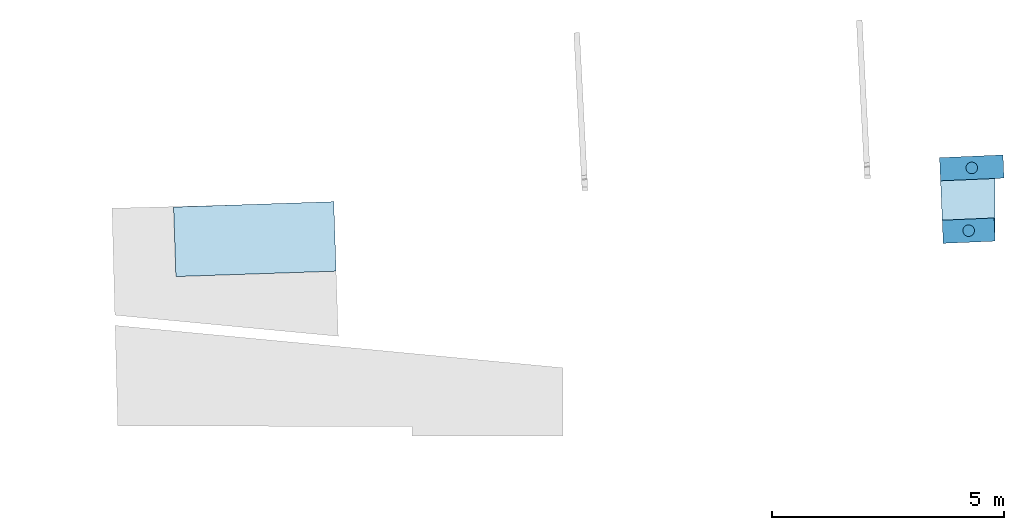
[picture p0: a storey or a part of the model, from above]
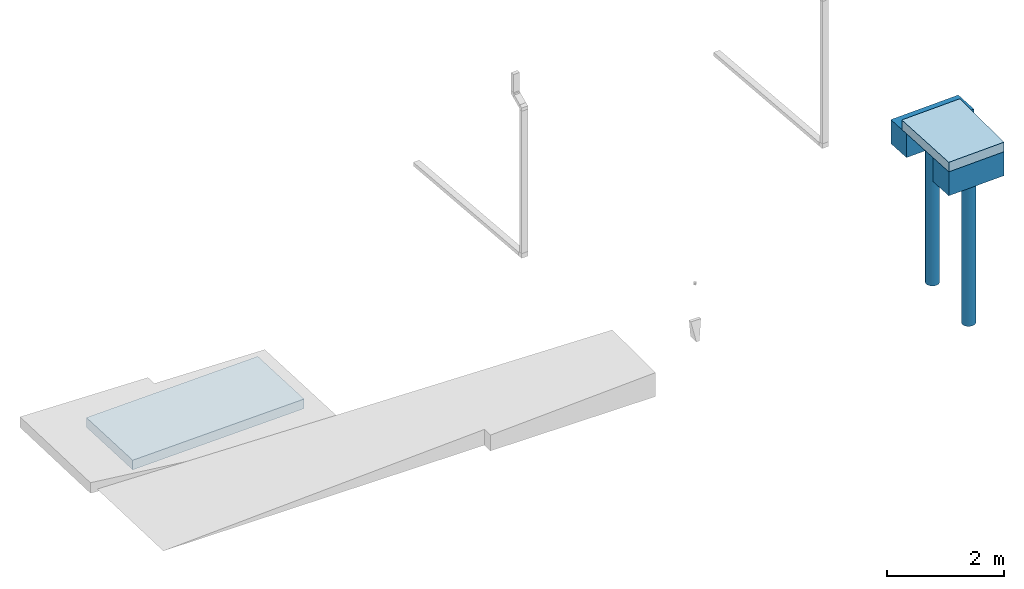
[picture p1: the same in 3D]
Properties of the parts of a building model (IFC2X3), part 1 of 2

# File
Description: ViewDefinition [CoordinationView_V2.0], RevitIdentifiers [ContentGUID: f51560e6-62e8-4d9f-ab56-705ca6fd7212, VersionGUID: 3fd126d5-c997-4c15-8835-0f22745aed74, NumberOfSaves: 71], CoordinateReference [CoordinateBase: Coordonnées partagées actuelles]
File name: 735-CAF31-Ombrière-GO.ifc
Time: 2026-01-16T10:04:22+01:00
Written by: ODA SDAI 24.6
Made in: Autodesk Revit 24.3.10.22 (FRA) - IFC 24.3.20.8

# IfcProject, PRO-DCE
LongName: REAMENAGEMENT DU PARVIS DE LA CAF RUE RIQUET A TOULOUSE; Phase: Etat du projet

# IfcSite, Default
RefLatitude: 48, 51, 57, 604064; RefLongitude: 2, 19, 58, 799800; RefElevation: 0 m

# IfcBuilding
Pset_BuildingCommon - NumberOfStoreys: 3

# IfcBuildingStorey: Niveau:Pointe 8 mm (5)
Name | LongName | Elevation (m)
Fondations | Fondations | -4
00_RDC CAF | 00_RDC CAF | 2.49825e-13
01_N1 CAF | 01_N1 CAF | 4.58
02_N2 CAF | 02_N2 CAF | 7.78
03_N3 CAF | 03_N3 CAF | 10.98

# IfcBeam: Cornière à ailes égales:L150x10 (8)
In: 00_RDC CAF
Type - PredefinedType: BEAM
Type - Pset_BeamCommon - LoadBearing: yes
Material: Acier structurel - S235
Pset_BeamCommon - IsExternal: no; Reference: L150x10
Pset_QuantityTakeOff - Reference: L150x10; sets with these values: 2
Name (Cornière à ailes égales:L150x10:...) | Span (m) | Slope (deg)
832467 | 14.653 | 0.0601116
832659 | 6.1642 | 1.77828
833064 | 3.4381 | 1.77549
833366 | 8.3522 | 0.167103
833582 | 5.8561 | 0
833692 | 1.5976 | 0
834071 | 0.5004 | 0
834376 | 0.5 | 1.7764

# IfcBeam: HE-A:HEA100, HE-A:HEA100:660216
In: 00_RDC CAF
Type - PredefinedType: BEAM
Type - Pset_BeamCommon - LoadBearing: yes
Material: Acier structurel - S235
Pset_BeamCommon - IsExternal: no; Slope: 0 deg; Reference: HEA100; Span: 2.385 m
Pset_QuantityTakeOff - Reference: HEA100; sets with these values: 2

# IfcBeam: IPE:IPE200 (15)
Type - PredefinedType: BEAM
Type - Pset_BeamCommon - LoadBearing: yes
Material: Acier structurel - S235
Pset_BeamCommon - IsExternal: no; Reference: IPE200
Pset_QuantityTakeOff - Reference: IPE200; sets with these values: 2
Name (IPE:IPE200:...) | In | Span (m) | Slope (deg)
616958 | 00_RDC CAF | 4.1239 | 1.77319
624277 | 00_RDC CAF | 0.41 | 1.7764
628714 | 01_N1 CAF | 2.576 | 0.0750055
629145 | 00_RDC CAF | 3.7879 | 1.77825
629344 | 00_RDC CAF | 3.4029 | 1.77558
658623 | 00_RDC CAF | 3.9255 | 1.77629
658634 | 00_RDC CAF | 4.0177 | 1.77553
771490 | 00_RDC CAF | 0.3538 | 1.77537
771715 | 00_RDC CAF | 0.3217 | 1.77558
771726 | 00_RDC CAF | 0.3538 | 1.77825
771738 | 00_RDC CAF | 0.3538 | 1.77871
771752 | 00_RDC CAF | 0.3538 | 1.77552
771776 | 00_RDC CAF | 0.3538 | 1.77317
771792 | 00_RDC CAF | 0.3538 | 1.77828
772215 | 01_N1 CAF | 2.6493 | 0.0729307

# IfcBeam: IPE:IPE240 (5)
In: 00_RDC CAF
Type - PredefinedType: BEAM
Type - Pset_BeamCommon - LoadBearing: yes
Material: Acier structurel - S235
Pset_BeamCommon - IsExternal: no; Reference: IPE240
Pset_QuantityTakeOff - Reference: IPE240; sets with these values: 2
Name (IPE:IPE240:...) | Span (m) | Slope (deg)
613705 | 9.6487 | 0.0765205
615907 | 5.1558 | 0
616066 | 2.1489 | 0.167103
623851 | 4.2305 | 1.77828
625010 | 3.1307 | 1.77549

# IfcBeam: LL-Deux cornières:DCED50x5x10 (6)
In: 00_RDC CAF
Type - PredefinedType: BEAM; Material: Acier structurel - S235
Type - Pset_BeamCommon - LoadBearing: yes
Pset_BeamCommon - IsExternal: no; Reference: DCED50x5x10
Pset_QuantityTakeOff - Reference: DCED50x5x10; sets with these values: 2
Name (LL-Deux cornières:DCED50x5x10:...) | Span (m) | Slope (deg)
689709 | 4.673 | 1.52976
689858 | 4.508 | 1.50344
690037 | 3.53 | 1.21998
690201 | 3.806 | 1.52568
727463 | 4.814 | 1.5502
728095 | 4.763 | 1.48888

# IfcBuildingElementProxy: Eq_Elec_Colonne_Electrique:Eq_Elec_Colonne_Electrique_120x80mm (22)
In: 00_RDC CAF
Type - Material: <Unnamed>
Pset_BuildingElementProxyCommon - Reference: Eq_Elec_Colonne_Electrique_120x80mm; sets with these values: 2
Name (Eq_Elec_Colonne_Electrique:Eq_Elec_Colonne_Electrique_120x80mm:...)
459293
459294
459295
459296
459297
459298
459299
459300
459301
459302
459303
459304
459309
459310
459311
459312
459313
459711
459854
459855
459856
459857

# IfcBuildingElementProxy: Eq_Spe_Plafond_Acoustique_Suspendu:Eq_Spe_Plafond_Acoustique_Suspendu (4)
In: 00_RDC CAF
Type - Material: <Unnamed>
Pset_BuildingElementProxyCommon - Reference: Eq_Spe_Plafond_Acoustique_Suspendu; sets with these values: 2
Name (Eq_Spe_Plafond_Acoustique_Suspendu:Eq_Spe_Plafond_Acoustique_Suspendu:...)
459287
459288
459289
459290

# IfcBuildingElementProxy: Eq_Spe_Plafond_Acoustique_Suspendu:Eq_Spe_Plafond_Acoustique_Suspendu (3)
In: 00_RDC CAF
Type - Material: ARC - Mo - Blanc
Pset_BuildingElementProxyCommon - Reference: Eq_Spe_Plafond_Acoustique_Suspendu; sets with these values: 2
Name (Eq_Spe_Plafond_Acoustique_Suspendu:Eq_Spe_Plafond_Acoustique_Suspendu:...)
459285
459291
459292

# IfcBuildingElementProxy: Profil en relief:M_Profil_Relief_N1 (4)
In: 00_RDC CAF
Material: STR - Beton
Pset_BuildingElementProxyCommon - Reference: M_Profil_Relief_N1; sets with these values: 2
Name (Profil en relief:M_Profil_Relief_N1:...)
459726
459728
459730
459732

# IfcBuildingElementProxy: SENBON Lattice Fence_Reversible Unit_gap 50mm:千本格子リバーシブルユニット 隙間50㎜_H2000 (4)
In: 01_N1 CAF
Type - Material: blackebony
Pset_BuildingElementProxyCommon - Reference: 千本格子リバーシブルユニット 隙間50㎜_H2000; sets with these values: 2
Name (SENBON Lattice Fence_Reversible Unit_gap 50mm:千本格子リバーシブルユニット 隙間50㎜_H2000:...)
690378
729924
730252
730253

# IfcBuildingElementProxy: SENBON Lattice Fence_Reversible Unit_gap 50mm:千本格子リバーシブルユニット 隙間50㎜_H2400, SENBON Lattice Fence_Reversible Unit_gap 50mm:千本格子リバーシブルユニット 隙間50㎜_H2400:726934
In: 01_N1 CAF
Type - Material: blackebony
Pset_BuildingElementProxyCommon - Reference: 千本格子リバーシブルユニット 隙間50㎜_H2400; sets with these values: 2

# IfcColumn: Po_Beton_Rectangulaire:Po_Beton_Rectangulaire_350x400mm, Po_Beton_Rectangulaire:Po_Beton_Rectangulaire_350x400mm:459794
In: 00_RDC CAF
Type - PredefinedType: COLUMN; Material: STR - Beton
Type - Pset_ColumnCommon - LoadBearing: yes
Pset_ColumnCommon - IsExternal: no; Reference: Po_Beton_Rectangulaire_350x400mm
Pset_QuantityTakeOff - Reference: Po_Beton_Rectangulaire_350x400mm; sets with these values: 2

# IfcColumn: Po_Beton_Rectangulaire:Po_Beton_Rectangulaire_400x280mm, Po_Beton_Rectangulaire:Po_Beton_Rectangulaire_400x280mm:459831
In: 00_RDC CAF
Type - PredefinedType: COLUMN; Material: STR - Beton
Type - Pset_ColumnCommon - LoadBearing: yes
Pset_ColumnCommon - IsExternal: no; Reference: Po_Beton_Rectangulaire_400x280mm
Pset_QuantityTakeOff - Reference: Po_Beton_Rectangulaire_400x280mm; sets with these values: 2

# IfcColumn: Po_Beton_Rectangulaire:Po_Beton_Rectangulaire_420x420mm (3)
In: 00_RDC CAF
Type - PredefinedType: COLUMN; Material: STR - Beton
Type - Pset_ColumnCommon - LoadBearing: yes
Pset_ColumnCommon - IsExternal: no; Reference: Po_Beton_Rectangulaire_420x420mm
Pset_QuantityTakeOff - Reference: Po_Beton_Rectangulaire_420x420mm; sets with these values: 2
Name (Po_Beton_Rectangulaire:Po_Beton_Rectangulaire_420x420mm:...)
459618
459792
459793

# IfcColumn: Po_Beton_Rectangulaire:Po_Beton_Rectangulaire_450x300mm (2)
In: 00_RDC CAF
Type - PredefinedType: COLUMN; Material: STR - Beton
Type - Pset_ColumnCommon - LoadBearing: yes
Pset_ColumnCommon - IsExternal: no; Reference: Po_Beton_Rectangulaire_450x300mm
Pset_QuantityTakeOff - Reference: Po_Beton_Rectangulaire_450x300mm; sets with these values: 2
Name (Po_Beton_Rectangulaire:Po_Beton_Rectangulaire_450x300mm:...)
459796
460303

# IfcColumn: Po_Beton_Rectangulaire:Po_Beton_Rectangulaire_450x400mm, Po_Beton_Rectangulaire:Po_Beton_Rectangulaire_450x400mm:459818
In: 00_RDC CAF
Type - PredefinedType: COLUMN; Material: STR - Beton
Type - Pset_ColumnCommon - LoadBearing: yes
Pset_ColumnCommon - IsExternal: no; Reference: Po_Beton_Rectangulaire_450x400mm
Pset_QuantityTakeOff - Reference: Po_Beton_Rectangulaire_450x400mm; sets with these values: 2

# IfcColumn: Po_Beton_Rectangulaire:Po_Beton_Rectangulaire_500x250mm, Po_Beton_Rectangulaire:Po_Beton_Rectangulaire_500x250mm:459820
In: 00_RDC CAF
Type - PredefinedType: COLUMN; Material: STR - Beton
Type - Pset_ColumnCommon - LoadBearing: yes
Pset_ColumnCommon - IsExternal: no; Reference: Po_Beton_Rectangulaire_500x250mm
Pset_QuantityTakeOff - Reference: Po_Beton_Rectangulaire_500x250mm; sets with these values: 2

# IfcColumn: Po_Beton_Rectangulaire:Po_Beton_Rectangulaire_520x420mm, Po_Beton_Rectangulaire:Po_Beton_Rectangulaire_520x420mm:459608
In: 00_RDC CAF
Type - PredefinedType: COLUMN; Material: STR - Beton
Type - Pset_ColumnCommon - LoadBearing: yes
Pset_ColumnCommon - IsExternal: no; Reference: Po_Beton_Rectangulaire_520x420mm
Pset_QuantityTakeOff - Reference: Po_Beton_Rectangulaire_520x420mm; sets with these values: 2

# IfcColumn: Po_Beton_Rectangulaire:Po_Beton_Rectangulaire_530x250mm, Po_Beton_Rectangulaire:Po_Beton_Rectangulaire_530x250mm:460304
In: 00_RDC CAF
Type - PredefinedType: COLUMN; Material: STR - Beton
Type - Pset_ColumnCommon - LoadBearing: yes
Pset_ColumnCommon - IsExternal: no; Reference: Po_Beton_Rectangulaire_530x250mm
Pset_QuantityTakeOff - Reference: Po_Beton_Rectangulaire_530x250mm; sets with these values: 2

# IfcColumn: Po_Beton_Rectangulaire:Po_Beton_Rectangulaire_550x370mm, Po_Beton_Rectangulaire:Po_Beton_Rectangulaire_550x370mm:459795
In: 00_RDC CAF
Type - PredefinedType: COLUMN; Material: STR - Beton
Type - Pset_ColumnCommon - LoadBearing: yes
Pset_ColumnCommon - IsExternal: no; Reference: Po_Beton_Rectangulaire_550x370mm
Pset_QuantityTakeOff - Reference: Po_Beton_Rectangulaire_550x370mm; sets with these values: 2

# IfcColumn: Po_Beton_Rectangulaire:Po_Beton_Rectangulaire_600x300mm (3)
In: 00_RDC CAF
Type - PredefinedType: COLUMN; Material: STR - Beton
Type - Pset_ColumnCommon - LoadBearing: yes
Pset_ColumnCommon - IsExternal: no; Reference: Po_Beton_Rectangulaire_600x300mm
Pset_QuantityTakeOff - Reference: Po_Beton_Rectangulaire_600x300mm; sets with these values: 2
Name (Po_Beton_Rectangulaire:Po_Beton_Rectangulaire_600x300mm:...)
459829
460256
460257

# IfcColumn: Po_Béton_Creusé _Bord:365mm x 385mm (5)
In: 00_RDC CAF
Type - PredefinedType: COLUMN; Material: STR - Beton
Type - Pset_ColumnCommon - LoadBearing: yes
Pset_ColumnCommon - IsExternal: no; Reference: 365mm x 385mm
Pset_QuantityTakeOff - Reference: 365mm x 385mm; sets with these values: 2
Name (Po_Béton_Creusé _Bord:365mm x 385mm:...)
458540
458543
460254
460459
460603

# IfcColumn: Po_Béton_Creusé_Courant:365mm x 385mm (25)
In: 00_RDC CAF
Type - PredefinedType: COLUMN; Material: STR - Beton
Type - Pset_ColumnCommon - LoadBearing: yes
Pset_ColumnCommon - IsExternal: no; Reference: 365mm x 385mm
Pset_QuantityTakeOff - Reference: 365mm x 385mm; sets with these values: 2
Name (Po_Béton_Creusé_Courant:365mm x 385mm:...)
458541
458542
458544
458545
458546
458547
458548
458549
458550
458551
458552
458553
458554
460460
460461
460462
460463
460464
460465
460604
460605
460606
460607
460608
460609

# IfcColumn: Po_Béton_T:365mm x 385mm (26)
In: 00_RDC CAF
Type - PredefinedType: COLUMN; Material: <Unnamed>
Type - Pset_ColumnCommon - LoadBearing: yes
Pset_ColumnCommon - IsExternal: no; Reference: 365mm x 385mm
Pset_QuantityTakeOff - Reference: 365mm x 385mm; sets with these values: 2
Name (Po_Béton_T:365mm x 385mm:...)
458565
458567
458568
458569
458570
458571
458572
458573
458574
458575
458576
458577
459950
459951
460466
460467
460468
460469
460470
460471
460610
460611
460612
460613
460614
460615

# IfcColumn: Poteau HE-A:HEA100 (2)
In: 00_RDC CAF
Type - PredefinedType: COLUMN; Material: Acier structurel - S235
Type - Pset_ColumnCommon - LoadBearing: yes
Pset_ColumnCommon - IsExternal: no; Reference: HEA100
Pset_QuantityTakeOff - Reference: HEA100; sets with these values: 2
Name (Poteau HE-A:HEA100:...)
659574 | Pset_ColumnCommon - Slope: 0 deg
729567

# IfcColumn: Poteau HE-A:HEA120 (5)
In: 00_RDC CAF
Type - PredefinedType: COLUMN; Material: Acier structurel - S235
Type - Pset_ColumnCommon - LoadBearing: yes
Pset_ColumnCommon - IsExternal: no; Slope: 0 deg; Reference: HEA120
Pset_QuantityTakeOff - Reference: HEA120; sets with these values: 2
Name (Poteau HE-A:HEA120:...)
609685
610124
610207
614403
614412

# IfcColumn: Poteau HE-B:HEB100 (5)
In: 00_RDC CAF
Type - PredefinedType: COLUMN; Material: STR - Acier
Type - Pset_ColumnCommon - LoadBearing: yes
Pset_ColumnCommon - IsExternal: no; Reference: HEB100
Pset_QuantityTakeOff - Reference: HEB100; sets with these values: 2
Name (Poteau HE-B:HEB100:...)
459441
459442
459443
459539
459540

# IfcCovering: Faux-Plafond_CAF:Faux-Plafond_CAF, Faux-Plafond_CAF:Faux-Plafond_CAF:458936
In: 00_RDC CAF
Type - PredefinedType: CEILING
Pset_CoveringCommon - Reference: Faux-Plafond_CAF; sets with these values: 2

# IfcCovering: Mur de base:FP_Platre_20mm_Joue_de_plafond (5)
In: 00_RDC CAF
Type - PredefinedType: CEILING; Material: ARC - FP - Blanc 0.02 m
Pset_CoveringCommon - Reference: FP_Platre_20mm_Joue_de_plafond; sets with these values: 2
Name (Mur de base:FP_Platre_20mm_Joue_de_plafond:...)
458953
459178
459197
459819
459888

# IfcCovering: Mur de base:FP_Platre_70mm_Joue_de_plafond (6)
In: 00_RDC CAF
Type - PredefinedType: CEILING; Material: ARC - FP - Blanc 0.07 m
Pset_CoveringCommon - Reference: FP_Platre_70mm_Joue_de_plafond; sets with these values: 2
Name (Mur de base:FP_Platre_70mm_Joue_de_plafond:...)
459209
459690
459691
459692
459693
459826

# IfcCovering: Plafond composé:FP_70mm (2)
In: 00_RDC CAF
Type - PredefinedType: CEILING
Type - Pset_CoveringCommon - TotalThickness: 0.07 m
Material: ARC - FP - Blanc 0.07 m
Pset_CoveringCommon - Reference: FP_70mm; sets with these values: 2
Name (Plafond composé:FP_70mm:...)
458963
459173

# IfcCovering: Plafond composé:FP_Dalle-600X600_70mm (21)
In: 00_RDC CAF
Type - PredefinedType: CEILING
Type - Pset_CoveringCommon - TotalThickness: 0.07 m
Material: ARC - FP - Blanc 0.02 m, ARC - FP - Trame 600 x 600 0.05 m
Pset_CoveringCommon - Reference: FP_Dalle-600X600_70mm; sets with these values: 2
Name (Plafond composé:FP_Dalle-600X600_70mm:...)
458870
458884
458892
458939
458946
458991
459024
459072
459084
459092
459117
459123
459153
459181
459192
459202
459318
459325
459682
460212
460221

# IfcCurtainWall: Mur-rideau:F.Ri._Ext_Vitre_40mm_Montant_100mm (4)
In: 00_RDC CAF
Pset_CurtainWallCommon - IsExternal: yes; Reference: F.Ri._Ext_Vitre_40mm_Montant_100mm
Pset_QuantityTakeOff - Reference: F.Ri._Ext_Vitre_40mm_Montant_100mm
Name (Mur-rideau:F.Ri._Ext_Vitre_40mm_Montant_100mm:...)
459893
459952
709813
709819

# IfcCurtainWall: Mur-rideau:FRi.Ext.30mm Etages (24)
In: 00_RDC CAF
Pset_CurtainWallCommon - IsExternal: yes; Reference: FRi.Ext.30mm Etages
Pset_QuantityTakeOff - Reference: FRi.Ext.30mm Etages
Name (Mur-rideau:FRi.Ext.30mm Etages:...)
460472
460481
460490
460499
460508
460517
460526
460535
460544
460553
460562
460571
460616
460625
460634
460643
460652
460661
460670
460679
460688
460697
460706
460715

# IfcCurtainWall: Mur-rideau:FRi.Ext.30mm RDC (28)
In: 00_RDC CAF
Pset_CurtainWallCommon - IsExternal: yes; Reference: FRi.Ext.30mm RDC
Pset_QuantityTakeOff - Reference: FRi.Ext.30mm RDC
Name (Mur-rideau:FRi.Ext.30mm RDC:...)
458555
458579
458589
458600
458611
458622
458633
458644
458655
458666
458677
458688
458699
458710
458716
458722
458733
458744
458755
458766
458777
458788
458799
458810
459980
459986
459992
459998

# IfcCurtainWall: Mur-rideau:M.Ri._Vitre_40mm_Montant_115mm, Mur-rideau:M.Ri._Vitre_40mm_Montant_115mm:459907
In: 00_RDC CAF
Pset_CurtainWallCommon - IsExternal: no; Reference: M.Ri._Vitre_40mm_Montant_115mm
Pset_QuantityTakeOff - Reference: M.Ri._Vitre_40mm_Montant_115mm

# IfcCurtainWall: Mur-rideau:M.Ri_Ext_Grille_RDC_50mm, Mur-rideau:M.Ri_Ext_Grille_RDC_50mm:460416
In: 00_RDC CAF
Pset_CurtainWallCommon - IsExternal: yes; Reference: M.Ri_Ext_Grille_RDC_50mm
Pset_QuantityTakeOff - Reference: M.Ri_Ext_Grille_RDC_50mm

# IfcCurtainWall: Mur-rideau:M.Ri_Vitre_40mm_Montant_50X50mm_Avec_Décalage (2)
In: 00_RDC CAF
Pset_CurtainWallCommon - IsExternal: no; Reference: M.Ri_Vitre_40mm_Montant_50X50mm_Avec_Décalage
Pset_QuantityTakeOff - Reference: M.Ri_Vitre_40mm_Montant_50X50mm_Avec_Décalage
Name (Mur-rideau:M.Ri_Vitre_40mm_Montant_50X50mm_Avec_Décalage:...)
459713
459750

# IfcCurtainWall: Mur-rideau:M.Ri_Vitre_40mm_Montant_70X90mm (5)
In: 00_RDC CAF
Pset_CurtainWallCommon - IsExternal: no; Reference: M.Ri_Vitre_40mm_Montant_70X90mm
Pset_QuantityTakeOff - Reference: M.Ri_Vitre_40mm_Montant_70X90mm
Name (Mur-rideau:M.Ri_Vitre_40mm_Montant_70X90mm:...)
458839
459337
459362
459387
459412

# IfcCurtainWall: Mur-rideau:M.Ri_Vitré_70mm, Mur-rideau:M.Ri_Vitré_70mm:459870
In: 00_RDC CAF
Pset_CurtainWallCommon - IsExternal: no; Reference: M.Ri_Vitré_70mm
Pset_QuantityTakeOff - Reference: M.Ri_Vitré_70mm

# IfcDistributionPort (57)
Description: Flow; FlowDirection: SOURCEANDSINK
Name | Group
Port_458968_1
Port_458977_1
Port_459947_1
Port_460020_1
Port_460022_1
Port_460023_1
Port_460025_1
Port_460069_1
Port_460070_1
Port_460073_1
Port_460074_1
Port_460076_1
Port_460077_1
Port_460079_1
Port_460080_1
Port_460081_1
Port_460082_1
Port_460083_1
Port_460084_1
Port_460085_1
Port_460086_1
Port_460087_1
Port_460088_1
Port_460089_1
Port_460090_1
Port_460091_1
Port_460092_1
Port_752365_0 | EP GO 2
Port_752365_1 | EP GO 2
Port_819100_0 | SF 2
Port_819140_1 | SF 2
Port_819100_1 | SF 2
Port_819104_1 | SF 2
Port_819101_0 | SF 2
Port_819140_2 | SF 2
Port_819101_1 | SF 2
Port_819103_0 | SF 2
Port_819104_2 | SF 2
Port_819103_1 | SF 2
Port_819106_1 | SF 2
Port_819105_0 | SF 2
Port_819106_2 | SF 2
Port_819105_1 | SF 2
Port_819262_0 | SF 1
Port_819268_1 | SF 1
Port_819262_1 | SF 1
Port_819265_1 | SF 1
Port_819263_0 | SF 1
Port_819268_2 | SF 1
Port_819263_1 | SF 1
Port_819264_0 | SF 1
Port_819265_2 | SF 1
Port_819264_1 | SF 1
Port_819267_1 | SF 1
Port_819266_0 | SF 1
Port_819267_2 | SF 1
Port_819266_1 | SF 1

# IfcDoor: P_Ascenseur:P_Int_Ascenseur_800x1980mm, P_Ascenseur:P_Int_Ascenseur_800x1980mm:459568
In: 00_RDC CAF
Type - ParameterTakesPrecedence: no; Sizeable: no; Material: ARC - M.In - Blanc
OverallHeight: 2.06 m; OverallWidth: 0.99 m
Pset_DoorCommon - IsExternal: no; Reference: P_Int_Ascenseur_800x1980mm
Pset_QuantityTakeOff - Reference: P_Int_Ascenseur_800x1980mm

# IfcDoor: P_Ascenseur:P_Int_Ascenseur_830x2150mm (2)
In: 00_RDC CAF
Type - ParameterTakesPrecedence: no; Sizeable: no; Material: ARC - M.In - Blanc
OverallHeight: 2.16 m; OverallWidth: 1.66 m
Pset_DoorCommon - IsExternal: no; Reference: P_Int_Ascenseur_830x2150mm
Pset_QuantityTakeOff - Reference: P_Int_Ascenseur_830x2150mm
Name (P_Ascenseur:P_Int_Ascenseur_830x2150mm:...)
459573
459574

# IfcDoor: P_Baie_Coulissante:P_Ext_Baie_Coulissante_2760x2450mm, P_Baie_Coulissante:P_Ext_Baie_Coulissante_2760x2450mm:459882
In: 00_RDC CAF
Type - ParameterTakesPrecedence: no; Sizeable: no; Material: ARC - M.In - Verre, ARC - M.In - Blanc
OverallHeight: 2.45 m; OverallWidth: 2.86 m
Pset_DoorCommon - IsExternal: yes; Reference: P_Ext_Baie_Coulissante_2760x2450mm
Pset_QuantityTakeOff - Reference: P_Ext_Baie_Coulissante_2760x2450mm

# IfcDoor: P_Coulissante_Applique:P_Ext_Coulissante_Applique_Pleine_980x2040mm, P_Coulissante_Applique:P_Ext_Coulissante_Applique_Pleine_980x2040mm:460972
In: 00_RDC CAF
Type - OperationType: SLIDING_TO_LEFT; ParameterTakesPrecedence: no; Sizeable: no; Material: ARC - M.Ex - Blanc, ARC - M.Ex - Verre
Type - P_Coulissante_Applique:P_Ext_Coulissante_Applique_Pleine_980x2040mm:460972:1 - PanelOperation: SLIDING
Type - Pset_DoorCommon - ThermalTransmittance: 3.7021 kg/K/s3
OverallHeight: 2.04 m; OverallWidth: 1.01 m
Pset_DoorCommon - IsExternal: yes; Reference: P_Ext_Coulissante_Applique_Pleine_980x2040mm
Pset_QuantityTakeOff - Reference: P_Ext_Coulissante_Applique_Pleine_980x2040mm

# IfcDoor: P_Coulissante_Applique_Double:P_Ext_Coulissante_Applique_Double_Vitree_1820x2190mm, P_Coulissante_Applique_Double:P_Ext_Coulissante_Applique_Double_Vitree_1820x2190mm:459886
In: 00_RDC CAF
Type - ParameterTakesPrecedence: no; Sizeable: no; Material: ARC - M.Ex - Verre, ARC - M.Ex - Blanc
OverallHeight: 2.23 m; OverallWidth: 3.64 m
Pset_DoorCommon - IsExternal: no; Reference: P_Ext_Coulissante_Applique_Double_Vitree_1820x2190mm
Pset_QuantityTakeOff - Reference: P_Ext_Coulissante_Applique_Double_Vitree_1820x2190mm

# IfcDoor: P_Coulissante_Applique_Double:P_Ext_Coulissante_Applique_Double_Vitree_2100x2450mm, P_Coulissante_Applique_Double:P_Ext_Coulissante_Applique_Double_Vitree_2100x2450mm:709812
In: 00_RDC CAF
Type - ParameterTakesPrecedence: no; Sizeable: no; Material: ARC - M.Ex - Verre, ARC - M.Ex - Blanc
OverallHeight: 2.45 m; OverallWidth: 2.1 m
Pset_DoorCommon - IsExternal: yes; Reference: P_Ext_Coulissante_Applique_Double_Vitree_2100x2450mm
Pset_QuantityTakeOff - Reference: P_Ext_Coulissante_Applique_Double_Vitree_2100x2450mm

# IfcDoor: P_Recouvrement_Double:P_Int_Double_Pleine_1260x2090mm (2)
In: 00_RDC CAF
Type - ParameterTakesPrecedence: no; Sizeable: no; Material: ARC - M.In - Blanc
Type - Pset_DoorCommon - ThermalTransmittance: 3.6886 kg/K/s3
OverallHeight: 2.125 m; OverallWidth: 1.33 m
Pset_DoorCommon - IsExternal: no; Reference: P_Int_Double_Pleine_1260x2090mm
Pset_QuantityTakeOff - Reference: P_Int_Double_Pleine_1260x2090mm
Name (P_Recouvrement_Double:P_Int_Double_Pleine_1260x2090mm:...)
459571
459572

# IfcDoor: P_Recouvrement_Simple:P_Int_Simple_Pleine_900x2040mm (3)
In: 00_RDC CAF
Type - ParameterTakesPrecedence: no; Sizeable: no; Material: ARC - M.In - Blanc
OverallHeight: 2.075 m; OverallWidth: 0.97 m
Pset_DoorCommon - IsExternal: no; Reference: P_Int_Simple_Pleine_900x2040mm
Pset_QuantityTakeOff - Reference: P_Int_Simple_Pleine_900x2040mm
Name (P_Recouvrement_Simple:P_Int_Simple_Pleine_900x2040mm:...)
459939
459940
459945

# IfcDoor: P_Recouvrement_Simple:P_Int_Simple_Pleine_940x2080mm, P_Recouvrement_Simple:P_Int_Simple_Pleine_940x2080mm:459569
In: 00_RDC CAF
Type - ParameterTakesPrecedence: no; Sizeable: no; Material: ARC - M.In - Blanc, ARC - M.In - Verre
OverallHeight: 2.115 m; OverallWidth: 1.01 m
Pset_DoorCommon - IsExternal: no; Reference: P_Int_Simple_Pleine_940x2080mm
Pset_QuantityTakeOff - Reference: P_Int_Simple_Pleine_940x2080mm

# IfcDoor: P_Ri_Coulissante_1V_Applique:P_M.Ri_Int_Coulissante_1V_Plein_Applique_40mm (2)
In: 00_RDC CAF
Type - ParameterTakesPrecedence: no; Sizeable: no; Material: ARC - M.In - Blanc
OverallHeight: 1.9525 m
Pset_DoorCommon - IsExternal: no; Reference: P_M.Ri_Int_Coulissante_1V_Plein_Applique_40mm
Pset_QuantityTakeOff - Reference: P_M.Ri_Int_Coulissante_1V_Plein_Applique_40mm
Name (P_Ri_Coulissante_1V_Applique:P_M.Ri_Int_Coulissante_1V_Plein_Applique_40mm:...) | OverallWidth (m)
459720 | 1.65
459757 | 1.96068

# IfcDoor: P_Ri_Simple:P_M-Ri_Int_Simple_Pleine_40mm, P_Ri_Simple:P_M-Ri_Int_Simple_Pleine_40mm:458853
In: 00_RDC CAF
Type - OperationType: SINGLE_SWING_LEFT; ParameterTakesPrecedence: no; Sizeable: no; Material: ARC - M.In - Blanc
Type - P_Ri_Simple:P_M-Ri_Int_Simple_Pleine_40mm:458853:1 - PanelOperation: SWINGING
OverallHeight: 2.04 m; OverallWidth: 0.900818 m
Pset_DoorCommon - IsExternal: no; Reference: P_M-Ri_Int_Simple_Pleine_40mm
Pset_QuantityTakeOff - Reference: P_M-Ri_Int_Simple_Pleine_40mm

# IfcDoor: P_Ri_Simple:P_M-Ri_Int_Simple_Pleine_40mm, P_Ri_Simple:P_M-Ri_Int_Simple_Pleine_40mm:459351
In: 00_RDC CAF
Type - OperationType: SINGLE_SWING_LEFT; ParameterTakesPrecedence: no; Sizeable: no; Material: ARC - M.In - Blanc
Type - P_Ri_Simple:P_M-Ri_Int_Simple_Pleine_40mm:459351:1 - PanelOperation: SWINGING
OverallHeight: 2.04 m; OverallWidth: 0.900812 m
Pset_DoorCommon - IsExternal: no; Reference: P_M-Ri_Int_Simple_Pleine_40mm
Pset_QuantityTakeOff - Reference: P_M-Ri_Int_Simple_Pleine_40mm

# IfcDoor: P_Ri_Simple:P_M-Ri_Int_Simple_Pleine_40mm, P_Ri_Simple:P_M-Ri_Int_Simple_Pleine_40mm:459376
In: 00_RDC CAF
Type - OperationType: SINGLE_SWING_LEFT; ParameterTakesPrecedence: no; Sizeable: no; Material: ARC - M.In - Blanc
Type - P_Ri_Simple:P_M-Ri_Int_Simple_Pleine_40mm:459376:1 - PanelOperation: SWINGING
OverallHeight: 2.04 m; OverallWidth: 0.959095 m
Pset_DoorCommon - IsExternal: no; Reference: P_M-Ri_Int_Simple_Pleine_40mm
Pset_QuantityTakeOff - Reference: P_M-Ri_Int_Simple_Pleine_40mm

# IfcDoor: P_Ri_Simple:P_M-Ri_Int_Simple_Pleine_40mm, P_Ri_Simple:P_M-Ri_Int_Simple_Pleine_40mm:459401
In: 00_RDC CAF
Type - OperationType: SINGLE_SWING_LEFT; ParameterTakesPrecedence: no; Sizeable: no; Material: ARC - M.In - Blanc
Type - P_Ri_Simple:P_M-Ri_Int_Simple_Pleine_40mm:459401:1 - PanelOperation: SWINGING
OverallHeight: 2.04 m; OverallWidth: 0.900579 m
Pset_DoorCommon - IsExternal: no; Reference: P_M-Ri_Int_Simple_Pleine_40mm
Pset_QuantityTakeOff - Reference: P_M-Ri_Int_Simple_Pleine_40mm

# IfcDoor: P_Ri_Simple:P_M-Ri_Int_Simple_Pleine_40mm, P_Ri_Simple:P_M-Ri_Int_Simple_Pleine_40mm:459426
In: 00_RDC CAF
Type - OperationType: SINGLE_SWING_LEFT; ParameterTakesPrecedence: no; Sizeable: no; Material: ARC - M.In - Blanc
Type - P_Ri_Simple:P_M-Ri_Int_Simple_Pleine_40mm:459426:1 - PanelOperation: SWINGING
OverallHeight: 2.04 m; OverallWidth: 0.905585 m
Pset_DoorCommon - IsExternal: no; Reference: P_M-Ri_Int_Simple_Pleine_40mm
Pset_QuantityTakeOff - Reference: P_M-Ri_Int_Simple_Pleine_40mm

# IfcDoor: P_Ri_barreau:P_M-Ri_Ext_Barreau_50mm, P_Ri_barreau:P_M-Ri_Ext_Barreau_50mm:460417
In: 00_RDC CAF
Type - OperationType: SINGLE_SWING_RIGHT; ParameterTakesPrecedence: no; Sizeable: no; Material: ARC - M.Ex - Blanc
Type - P_Ri_barreau:P_M-Ri_Ext_Barreau_50mm:460417:1 - PanelOperation: SWINGING
OverallHeight: 2.395 m; OverallWidth: 2.16 m
Pset_DoorCommon - IsExternal: yes; Reference: P_M-Ri_Ext_Barreau_50mm
Pset_QuantityTakeOff - Reference: P_M-Ri_Ext_Barreau_50mm

# IfcDoor: P_Tunnel_Double:P_Int_Double_Pleine_1530x2040mm, P_Tunnel_Double:P_Int_Double_Pleine_1530x2040mm:460415
In: 00_RDC CAF
Type - OperationType: DOUBLE_DOOR_SINGLE_SWING; ParameterTakesPrecedence: no; Sizeable: no; Material: ARC - M.In - Blanc
Type - P_Tunnel_Double:P_Int_Double_Pleine_1530x2040mm:460415:1 - PanelOperation: SWINGING
Type - Pset_DoorCommon - ThermalTransmittance: 3.6886 kg/K/s3
OverallHeight: 2.075 m; OverallWidth: 1.6 m
Pset_DoorCommon - IsExternal: no; Reference: P_Int_Double_Pleine_1530x2040mm
Pset_QuantityTakeOff - Reference: P_Int_Double_Pleine_1530x2040mm

# IfcDoor: P_Tunnel_Simple:P_Int_Simple_Pleine_700x2060mm, P_Tunnel_Simple:P_Int_Simple_Pleine_700x2060mm:459916
In: 00_RDC CAF
Type - ParameterTakesPrecedence: no; Sizeable: no; Material: ARC - M.In - Blanc
Type - Pset_DoorCommon - ThermalTransmittance: 3.7021 kg/K/s3
OverallHeight: 2.105 m; OverallWidth: 0.79 m
Pset_DoorCommon - IsExternal: no; Reference: P_Int_Simple_Pleine_700x2060mm
Pset_QuantityTakeOff - Reference: P_Int_Simple_Pleine_700x2060mm

# IfcDoor: P_Tunnel_Simple:P_Int_Simple_Pleine_930x1970mm, P_Tunnel_Simple:P_Int_Simple_Pleine_930x1970mm:459452
In: 00_RDC CAF
Type - ParameterTakesPrecedence: no; Sizeable: no; Material: ARC - M.In - Blanc
Type - Pset_DoorCommon - ThermalTransmittance: 3.7021 kg/K/s3
OverallHeight: 2.005 m; OverallWidth: 1 m
Pset_DoorCommon - IsExternal: no; Reference: P_Int_Simple_Pleine_930x1970mm
Pset_QuantityTakeOff - Reference: P_Int_Simple_Pleine_930x1970mm

# IfcDoor: P_Tunnel_Simple:P_Int_Simple_Pleine_930x2040mm, P_Tunnel_Simple:P_Int_Simple_Pleine_930x2040mm:459619
In: 00_RDC CAF
Type - ParameterTakesPrecedence: no; Sizeable: no; Material: ARC - M.In - Blanc
Type - Pset_DoorCommon - ThermalTransmittance: 3.7021 kg/K/s3
OverallHeight: 2.07275 m; OverallWidth: 0.995505 m
Pset_DoorCommon - IsExternal: no; Reference: P_Int_Simple_Pleine_930x2040mm
Pset_QuantityTakeOff - Reference: P_Int_Simple_Pleine_930x2040mm

# IfcDoor: P_Tunnel_Simple:P_Int_Simple_Pleine_930x2090mm (2)
In: 00_RDC CAF
Type - ParameterTakesPrecedence: no; Sizeable: no; Material: ARC - M.In - Blanc
Type - Pset_DoorCommon - ThermalTransmittance: 3.7021 kg/K/s3
OverallHeight: 2.125 m; OverallWidth: 1 m
Pset_DoorCommon - IsExternal: no; Reference: P_Int_Simple_Pleine_930x2090mm
Pset_QuantityTakeOff - Reference: P_Int_Simple_Pleine_930x2090mm
Name (P_Tunnel_Simple:P_Int_Simple_Pleine_930x2090mm:...)
459021
459832

# IfcDoor: P_Tunnel_Simple:P_Int_Simple_Pleine_950x2090mm, P_Tunnel_Simple:P_Int_Simple_Pleine_950x2090mm:460165
In: 00_RDC CAF
Type - ParameterTakesPrecedence: no; Sizeable: no; Material: ARC - M.In - Blanc
Type - Pset_DoorCommon - ThermalTransmittance: 3.7021 kg/K/s3
OverallHeight: 2.12686 m; OverallWidth: 0.953723 m
Pset_DoorCommon - IsExternal: no; Reference: P_Int_Simple_Pleine_950x2090mm
Pset_QuantityTakeOff - Reference: P_Int_Simple_Pleine_950x2090mm

# IfcDoor: P_Tunnel_Tierce:P_Int_Tierce_Pleine_1380x2000mm, P_Tunnel_Tierce:P_Int_Tierce_Pleine_1380x2000mm:460307
In: 00_RDC CAF
Type - ParameterTakesPrecedence: no; Sizeable: no; Material: ARC - M.In - Blanc
Type - Pset_DoorCommon - ThermalTransmittance: 3.7021 kg/K/s3
OverallHeight: 2.035 m; OverallWidth: 1.45 m
Pset_DoorCommon - IsExternal: no; Reference: P_Int_Tierce_Pleine_1380x2000mm
Pset_QuantityTakeOff - Reference: P_Int_Tierce_Pleine_1380x2000mm

# IfcDoor: P_Tunnel_Tierce:P_Int_Tierce_Pleine_1620x2040mm, P_Tunnel_Tierce:P_Int_Tierce_Pleine_1620x2040mm:459671
In: 00_RDC CAF
Type - ParameterTakesPrecedence: no; Sizeable: no; Material: ARC - M.In - Blanc
Type - Pset_DoorCommon - ThermalTransmittance: 3.7021 kg/K/s3
OverallHeight: 2.075 m; OverallWidth: 1.69 m
Pset_DoorCommon - IsExternal: no; Reference: P_Int_Tierce_Pleine_1620x2040mm
Pset_QuantityTakeOff - Reference: P_Int_Tierce_Pleine_1620x2040mm

# IfcDoor: Po_Porte_sectionnelle:Po_Porte_sectionnelle_3400x2780mm, Po_Porte_sectionnelle:Po_Porte_sectionnelle_3400x2780mm:460414
In: 00_RDC CAF
Type - OperationType: ROLLINGUP; ParameterTakesPrecedence: no; Sizeable: no; Material: ARC - M.Ex - Tole, ARC - M.Ex - Blanc
Type - Po_Porte_sectionnelle:Po_Porte_sectionnelle_3400x2780mm:460414:1 - PanelOperation: ROLLINGUP
Type - Pset_DoorCommon - ThermalTransmittance: 3.7021 kg/K/s3
OverallHeight: 2.795 m; OverallWidth: 3.52 m
Pset_DoorCommon - IsExternal: yes; Reference: Po_Porte_sectionnelle_3400x2780mm
Pset_QuantityTakeOff - Reference: Po_Porte_sectionnelle_3400x2780mm

# IfcFlowController: Eq_CVC_Bouche_circulaire_soufflage_base carre:Eq_CVC_Bouche_circulaire_soufflage_D350mm_base carre_600x600mm (6)
In: 00_RDC CAF
Type - Material: ARC - Eq CVC - Blanc, <Unnamed>
Pset_DistributionFlowElementCommon - Reference: Eq_CVC_Bouche_circulaire_soufflage_D350mm_base carre_600x600mm; sets with these values: 2
Name (Eq_CVC_Bouche_circulaire_soufflage_base carre:Eq_CVC_Bouche_circulaire_soufflage_D350mm_base carre_600x600mm:...)
458999
459001
459002
459098
459099
459169

# IfcFlowController: Eq_CVC_Bouche_rectangulaire_soufflage_1_fente:Eq_CVC_Bouche_rectangulaire_soufflage_1_fente_1200x70mm (16)
In: 00_RDC CAF
Type - Material: <Unnamed>, ARC - Eq CVC - Blanc
Pset_DistributionFlowElementCommon - Reference: Eq_CVC_Bouche_rectangulaire_soufflage_1_fente_1200x70mm; sets with these values: 2
Name (Eq_CVC_Bouche_rectangulaire_soufflage_1_fente:Eq_CVC_Bouche_rectangulaire_soufflage_1_fente_1200x70mm:...)
458968
458977
460079
460080
460081
460082
460083
460084
460085
460086
460087
460088
460089
460090
460091
460092

# IfcFlowController: Eq_CVC_Climatisation murale:Eq_CVC_Climatisation murale_180x780x500mm, Eq_CVC_Climatisation murale:Eq_CVC_Climatisation murale_180x780x500mm:460137
In: 00_RDC CAF
Type - Material: <Unnamed>
Pset_DistributionFlowElementCommon - Reference: Eq_CVC_Climatisation murale_180x780x500mm; sets with these values: 2

# IfcFlowFitting: Coude Rectangulaire Droit:Standard (6)
In: Fondations
Type - Material: <Unnamed>
Pset_DistributionFlowElementCommon - Reference: Standard; sets with these values: 2
Name (Coude Rectangulaire Droit:Standard:...) | Group
819104 | SF 2
819106 | SF 2
819140 | SF 2
819265 | SF 1
819267 | SF 1
819268 | SF 1

# IfcFlowSegment: Canalisation:Par défaut, Canalisation:Par défaut:752365
In: 00_RDC CAF
Pset_DistributionFlowElementCommon - Reference: Par défaut; sets with these values: 2
Pset_FlowSegmentDuctSegment - Length: 3.87178 m; sets with these values: 2
Group: EP GO 2

# IfcFlowSegment: Gaine rectangulaire:Raccord avec té et coude droit (8)
In: Fondations
Pset_DistributionFlowElementCommon - Reference: Raccord avec té et coude droit; sets with these values: 2
Pset_FlowSegmentDuctSegment - sets with these values: 2
Name (Gaine rectangulaire:Raccord avec té et coude droit:...) | Length (m) | Group
819100 | 2.9742 | SF 2
819101 | 3.31824 | SF 2
819103 | 0.210517 | SF 2
819105 | 0.373349 | SF 2
819262 | 2.97435 | SF 1
819263 | 3.31067 | SF 1
819264 | 0.201772 | SF 1
819266 | 0.377722 | SF 1

# IfcFlowTerminal: Eq_Elec_Eclairage_secours_BAES:Eq_Elec_Eclairage secours BAES_220x35x100mm (2)
In: 00_RDC CAF
Type - Material: ARC - Eq Elec - Blanc
Pset_DistributionFlowElementCommon - Reference: Eq_Elec_Eclairage secours BAES_220x35x100mm; sets with these values: 2
Name (Eq_Elec_Eclairage_secours_BAES:Eq_Elec_Eclairage secours BAES_220x35x100mm:...)
460023
460025

# IfcFlowTerminal: Eq_Elec_Eclairage_secours_BAES:Eq_Elec_Eclairage secours BAES_240x35x100mm, Eq_Elec_Eclairage_secours_BAES:Eq_Elec_Eclairage secours BAES_240x35x100mm:460020
In: 00_RDC CAF
Type - Material: ARC - Eq Elec - Blanc
Pset_DistributionFlowElementCommon - Reference: Eq_Elec_Eclairage secours BAES_240x35x100mm; sets with these values: 2

# IfcFlowTerminal: Eq_Elec_Eclairage_secours_BAES:Eq_Elec_Eclairage secours BAES_240x40x120mm, Eq_Elec_Eclairage_secours_BAES:Eq_Elec_Eclairage secours BAES_240x40x120mm:459947
In: 00_RDC CAF
Type - Material: ARC - Eq Elec - Blanc
Pset_DistributionFlowElementCommon - Reference: Eq_Elec_Eclairage secours BAES_240x40x120mm; sets with these values: 2

# IfcFlowTerminal: Eq_Elec_Eclairage_secours_BAES:Eq_Elec_Eclairage secours BAES_240x50x120mm, Eq_Elec_Eclairage_secours_BAES:Eq_Elec_Eclairage secours BAES_240x50x120mm:460074
In: 00_RDC CAF
Type - Material: ARC - Eq Elec - Blanc
Pset_DistributionFlowElementCommon - Reference: Eq_Elec_Eclairage secours BAES_240x50x120mm; sets with these values: 2

# IfcFlowTerminal: Eq_Elec_Eclairage_secours_BAES:Eq_Elec_Eclairage secours BAES_260x160x35mm (5)
In: 00_RDC CAF
Type - Material: ARC - Eq Elec - Blanc
Pset_DistributionFlowElementCommon - Reference: Eq_Elec_Eclairage secours BAES_260x160x35mm; sets with these values: 2
Name (Eq_Elec_Eclairage_secours_BAES:Eq_Elec_Eclairage secours BAES_260x160x35mm:...)
460069
460070
460073
460076
460077

# IfcFlowTerminal: Eq_Elec_Eclairage_secours_BAES:Eq_Elec_Eclairage secours BAES_340x80x100mm, Eq_Elec_Eclairage_secours_BAES:Eq_Elec_Eclairage secours BAES_340x80x100mm:460022
In: 00_RDC CAF
Type - Material: ARC - Eq Elec - Blanc
Pset_DistributionFlowElementCommon - Reference: Eq_Elec_Eclairage secours BAES_340x80x100mm; sets with these values: 2

# IfcFlowTerminal: Eq_Elec_Luminaire_Carre_Neons_Encastre:Eq_Elec_Luminaire_Carre_Neons_Encastre_600x600x80mm (8)
In: 00_RDC CAF
Type - Material: ARC - Eq Elec - Blanc
Pset_DistributionFlowElementCommon - Reference: Eq_Elec_Luminaire_Carre_Neons_Encastre_600x600x80mm; sets with these values: 2
Name (Eq_Elec_Luminaire_Carre_Neons_Encastre:Eq_Elec_Luminaire_Carre_Neons_Encastre_600x600x80mm:...)
459140
459141
459142
459143
459148
459149
459150
459228

# IfcFlowTerminal: Eq_Elec_Luminaire_Circulaire_LED_Applique:Eq_Elec_Luminaire_Circulaire_LED_Applique_D220x50mm (2)
In: 00_RDC CAF
Type - Material: ARC - Eq Elec - Blanc
Pset_DistributionFlowElementCommon - Reference: Eq_Elec_Luminaire_Circulaire_LED_Applique_D220x50mm; sets with these values: 2
Name (Eq_Elec_Luminaire_Circulaire_LED_Applique:Eq_Elec_Luminaire_Circulaire_LED_Applique_D220x50mm:...)
460232
460234

# IfcFlowTerminal: Eq_Elec_Luminaire_Circulaire_LED_Encastre:Eq_Elec_Luminaire_Circulaire_LED_Encastre_D220x50mm (15)
In: 00_RDC CAF
Type - Material: ARC - Eq Elec - Blanc
Pset_DistributionFlowElementCommon - Reference: Eq_Elec_Luminaire_Circulaire_LED_Encastre_D220x50mm; sets with these values: 2
Name (Eq_Elec_Luminaire_Circulaire_LED_Encastre:Eq_Elec_Luminaire_Circulaire_LED_Encastre_D220x50mm:...)
458979
458980
458981
458983
458984
458985
458987
458988
459198
459199
459264
459265
459266
459672
459674

# IfcFlowTerminal: Eq_Elec_Luminaire_Rectangulaire_LED_Encastre:Eq_Elec_Luminaire_Rectangulaire_LED_Encastre_600x600x30mm (4)
In: 00_RDC CAF
Type - Material: ARC - Eq Elec - Blanc
Pset_DistributionFlowElementCommon - Reference: Eq_Elec_Luminaire_Rectangulaire_LED_Encastre_600x600x30mm; sets with these values: 2
Name (Eq_Elec_Luminaire_Rectangulaire_LED_Encastre:Eq_Elec_Luminaire_Rectangulaire_LED_Encastre_600x600x30mm:...)
459144
459145
459164
459166

# IfcFlowTerminal: Eq_Elec_Luminaire_Rectangulaire_Neons_Encastre:Eq_Elec_Luminaire_Rectangulaire_Neons_Encastre_590x300x75mm (7)
In: 00_RDC CAF
Type - Material: ARC - Eq Elec - Blanc
Pset_DistributionFlowElementCommon - Reference: Eq_Elec_Luminaire_Rectangulaire_Neons_Encastre_590x300x75mm; sets with these values: 2
Name (Eq_Elec_Luminaire_Rectangulaire_Neons_Encastre:Eq_Elec_Luminaire_Rectangulaire_Neons_Encastre_590x300x75mm:...)
458996
458997
459096
459100
459107
459108
459949

# IfcFlowTerminal: Eq_Elec_Luminaire_Rectangulaire_Neons_Encastre:Eq_Elec_Luminaire_Rectangulaire_Neons_Encastre_590x400x75mm (52)
In: 00_RDC CAF
Type - Material: ARC - Eq Elec - Blanc
Pset_DistributionFlowElementCommon - Reference: Eq_Elec_Luminaire_Rectangulaire_Neons_Encastre_590x400x75mm; sets with these values: 2
Name (Eq_Elec_Luminaire_Rectangulaire_Neons_Encastre:Eq_Elec_Luminaire_Rectangulaire_Neons_Encastre_590x400x75mm:...)
459210
459211
459212
459213
459214
459215
459216
459217
459218
459219
459220
459221
459222
459223
459224
459225
459226
459227
459229
459230
459231
459232
459233
459234
459235
459236
459237
459238
459239
459240
459241
459242
459243
459245
459247
459248
459249
459250
459251
459252
459253
459254
459255
459256
459257
459258
459259
459260
459261
459262
459765
459766

# IfcFlowTerminal: Eq_Elec_Luminaire_Reglette_LED_Applique:Eq_Elec_Luminaire_Reglette_LED_Applique_1500x76x80mm (2)
In: 00_RDC CAF
Type - Material: <Unnamed>
Pset_DistributionFlowElementCommon - Reference: Eq_Elec_Luminaire_Reglette_LED_Applique_1500x76x80mm; sets with these values: 2
Name (Eq_Elec_Luminaire_Reglette_LED_Applique:Eq_Elec_Luminaire_Reglette_LED_Applique_1500x76x80mm:...)
459476
459477

# IfcFlowTerminal: Eq_Elec_Luminaire_Trapezoïdal_LED_Suspension:Eq_Elec_Luminaire_Trapezoïdal_LED_Suspension_200x60mm (11)
In: Fondations
Type - Material: ARC - Eq Elec - Blanc
Pset_DistributionFlowElementCommon - Reference: Eq_Elec_Luminaire_Trapezoïdal_LED_Suspension_200x60mm; sets with these values: 2
Name (Eq_Elec_Luminaire_Trapezoïdal_LED_Suspension:Eq_Elec_Luminaire_Trapezoïdal_LED_Suspension_200x60mm:...)
459267
459268
459269
459270
459271
459272
459273
459274
459275
459276
459838

# IfcFlowTerminal: Eq_Plb_Lavabo_Monovasque:Eq_Plb_Lavabo_Monovasque_1000x600mm (3)
In: 00_RDC CAF
Type - Material: ARC - Plb - Blanc
Pset_DistributionFlowElementCommon - Reference: Eq_Plb_Lavabo_Monovasque_1000x600mm; sets with these values: 2
Name (Eq_Plb_Lavabo_Monovasque:Eq_Plb_Lavabo_Monovasque_1000x600mm:...)
459724
459725
459864

# IfcFlowTerminal: Eq_Plb_Lavabo_Monovasque:Eq_Plb_Lavabo_Monovasque_1770x600mm, Eq_Plb_Lavabo_Monovasque:Eq_Plb_Lavabo_Monovasque_1770x600mm:459733
In: 00_RDC CAF
Type - Material: ARC - Plb - Blanc
Pset_DistributionFlowElementCommon - Reference: Eq_Plb_Lavabo_Monovasque_1770x600mm; sets with these values: 2

# IfcFlowTerminal: Eq_Plb_WC:Eq_Plb_WC (3)
In: 00_RDC CAF
Type - Material: Porcelaine - Blanche, Métal - Chrome
Pset_DistributionFlowElementCommon - Reference: Eq_Plb_WC; sets with these values: 2
Name (Eq_Plb_WC:Eq_Plb_WC:...)
459913
459914
459915

# IfcFurnishingElement: Mo_Armoire_Porte_Coulissante:Mo_Armoire_Haute_1000x430x1800, Mo_Armoire_Porte_Coulissante:Mo_Armoire_Haute_1000x430x1800:459563
In: 00_RDC CAF
Type - Material: ARC - Mo - Blanc
Pset_QuantityTakeOff - Reference: Mo_Armoire_Haute_1000x430x1800

# IfcFurnishingElement: Mo_Armoire_Porte_Coulissante:Mo_Armoire_Haute_1000x430x2000mm (4)
In: 00_RDC CAF
Type - Material: ARC - Mo - Blanc
Pset_QuantityTakeOff - Reference: Mo_Armoire_Haute_1000x430x2000mm
Name (Mo_Armoire_Porte_Coulissante:Mo_Armoire_Haute_1000x430x2000mm:...)
459560
459562
459736
459737

# IfcFurnishingElement: Mo_Armoire_Porte_Coulissante:Mo_Armoire_Haute_1200x430x2000mm, Mo_Armoire_Porte_Coulissante:Mo_Armoire_Haute_1200x430x2000mm:459577
In: 00_RDC CAF
Type - Material: ARC - Mo - Blanc
Pset_QuantityTakeOff - Reference: Mo_Armoire_Haute_1200x430x2000mm

# IfcFurnishingElement: Mo_Armoire_Porte_Coulissante:Mo_Armoire_basse_1000x430x1000mm, Mo_Armoire_Porte_Coulissante:Mo_Armoire_basse_1000x430x1000mm:459576
In: 00_RDC CAF
Type - Material: ARC - Mo - Blanc
Pset_QuantityTakeOff - Reference: Mo_Armoire_basse_1000x430x1000mm

# IfcFurnishingElement: Mo_Armoire_Porte_Coulissante:Mo_Armoire_basse_1200x430x1000mm (2)
In: 00_RDC CAF
Type - Material: ARC - Mo - Blanc
Pset_QuantityTakeOff - Reference: Mo_Armoire_basse_1200x430x1000mm
Name (Mo_Armoire_Porte_Coulissante:Mo_Armoire_basse_1200x430x1000mm:...)
459561
459747

# IfcFurnishingElement: Mo_Armoire_Porte_Coulissante:Mo_Armoire_basse_2300x430x960mm (2)
In: 00_RDC CAF
Type - Material: ARC - Mo - Blanc
Pset_QuantityTakeOff - Reference: Mo_Armoire_basse_2300x430x960mm
Name (Mo_Armoire_Porte_Coulissante:Mo_Armoire_basse_2300x430x960mm:...)
460167
460168

# IfcFurnishingElement: Mo_Armoire_Porte_Coulissante:Mo_Armoire_basse_800x430x800mm, Mo_Armoire_Porte_Coulissante:Mo_Armoire_basse_800x430x800mm:459746
In: 00_RDC CAF
Type - Material: ARC - Mo - Blanc
Pset_QuantityTakeOff - Reference: Mo_Armoire_basse_800x430x800mm

# IfcFurnishingElement: Mo_Bureau:Mo_Bureau_1300x600mm (5)
In: 00_RDC CAF
Type - Material: ARC - Mo - Blanc
Pset_QuantityTakeOff - Reference: Mo_Bureau_1300x600mm
Name (Mo_Bureau:Mo_Bureau_1300x600mm:...)
459602
459609
459611
459613
460169

# IfcFurnishingElement: Mo_Bureau:Mo_Bureau_1400x600mm (2)
In: 00_RDC CAF
Type - Material: ARC - Mo - Blanc
Pset_QuantityTakeOff - Reference: Mo_Bureau_1400x600mm
Name (Mo_Bureau:Mo_Bureau_1400x600mm:...)
459600
459604

# IfcFurnishingElement: Mo_Bureau:Mo_Bureau_1600x700mm (4)
In: 00_RDC CAF
Type - Material: ARC - Mo - Blanc
Pset_QuantityTakeOff - Reference: Mo_Bureau_1600x700mm
Name (Mo_Bureau:Mo_Bureau_1600x700mm:...)
459586
459588
459590
459744

# IfcFurnishingElement: Mo_Bureau:Mo_Bureau_1600x800mm (5)
In: 00_RDC CAF
Type - Material: ARC - Mo - Blanc
Pset_QuantityTakeOff - Reference: Mo_Bureau_1600x800mm
Name (Mo_Bureau:Mo_Bureau_1600x800mm:...)
459460
459462
459464
459564
459734

# IfcFurnishingElement: Mo_Bureau:Mo_Bureau_1800x800mm (4)
In: 00_RDC CAF
Type - Material: ARC - Mo - Blanc
Pset_QuantityTakeOff - Reference: Mo_Bureau_1800x800mm
Name (Mo_Bureau:Mo_Bureau_1800x800mm:...)
459592
459594
459596
459598

# IfcFurnishingElement: Mo_Bureau:Mo_Bureau_1800x900mm (12)
In: 00_RDC CAF
Type - Material: ARC - Mo - Blanc
Pset_QuantityTakeOff - Reference: Mo_Bureau_1800x900mm
Name (Mo_Bureau:Mo_Bureau_1800x900mm:...)
459466
459468
459470
459472
459474
459578
459580
459582
459584
459738
459740
459742

# IfcFurnishingElement: Mo_Bureau_L:Mo_Bureau_L_1600x1600mm, Mo_Bureau_L:Mo_Bureau_L_1600x1600mm:459558
In: 00_RDC CAF
Type - Material: ARC - Mo - Blanc
Pset_QuantityTakeOff - Reference: Mo_Bureau_L_1600x1600mm

# IfcFurnishingElement: Mo_Chaise_Bureau:Mo_Chaise_Bureau (33)
In: 00_RDC CAF
Type - Material: ARC - Mo - Blanc
Pset_QuantityTakeOff - Reference: Mo_Chaise_Bureau
Name (Mo_Chaise_Bureau:Mo_Chaise_Bureau:...)
459461
459463
459465
459467
459469
459471
459473
459475
459559
459565
459579
459581
459583
459585
459587
459589
459591
459593
459595
459597
459599
459601
459603
459605
459610
459612
459614
459735
459739
459741
459743
459745
460170

# IfcFurnishingElement: Mo_Comptoir_Accueil:Mo_Table_1100x400x1200mm, Mo_Comptoir_Accueil:Mo_Table_1100x400x1200mm:460193
In: 00_RDC CAF
Type - Material: ARC - Mo - Blanc
Pset_QuantityTakeOff - Reference: Mo_Table_1100x400x1200mm

# IfcFurnishingElement: Mo_Comptoir_Accueil:Mo_Table_1200x400x1200mm, Mo_Comptoir_Accueil:Mo_Table_1200x400x1200mm:460171
In: 00_RDC CAF
Type - Material: ARC - Mo - Blanc
Pset_QuantityTakeOff - Reference: Mo_Table_1200x400x1200mm

# IfcFurnishingElement: Mo_Comptoir_Accueil:Mo_Table_1300x400x1200mm (5)
In: 00_RDC CAF
Type - Material: ARC - Mo - Blanc
Pset_QuantityTakeOff - Reference: Mo_Table_1300x400x1200mm
Name (Mo_Comptoir_Accueil:Mo_Table_1300x400x1200mm:...)
459606
459607
459615
459616
459617

# IfcFurnishingElement: Mo_Table:Mo_Table_700x1300x900mm, Mo_Table:Mo_Table_700x1300x900mm:459575
In: 00_RDC CAF
Type - Material: ARC - Mo - Blanc
Pset_QuantityTakeOff - Reference: Mo_Table_700x1300x900mm

# IfcFurnishingElement: Mo_Table_Ronde_Pied_Central:Mo_Table_Haute_Ronde_D800x1200mm (2)
In: 00_RDC CAF
Type - Material: ARC - Mo - Blanc
Pset_QuantityTakeOff - Reference: Mo_Table_Haute_Ronde_D800x1200mm
Name (Mo_Table_Ronde_Pied_Central:Mo_Table_Haute_Ronde_D800x1200mm:...)
459748
459749

# IfcMember: Limon à crémaillère:Limon à crémaillère - Largeur 160 mm 2 (7)
In: 00_RDC CAF
Type - PredefinedType: STRINGER
Material: <Unnamed>
Pset_MemberCommon - IsExternal: no; Reference: Limon à crémaillère - Largeur 160 mm 2
Pset_QuantityTakeOff - Reference: Limon à crémaillère - Largeur 160 mm 2
Name (Escalier assemblé:Escalier:...) | Slope (deg)
459485 Stringer 1 | 31.2645
459485 Stringer 2 | 31.2645
459485 Stringer 3 | 31.2645
459485 Stringer 4 | 31.2645
459485 Stringer 5 | 31.2645
459485 Stringer 6 | 31.2645
459485 Stringer 7 | 0

# IfcMember: Meneau rectangulaire:F.Ri.M_Ext_Rectangulaire_100x100mm (16)
In: 00_RDC CAF
Type - PredefinedType: MULLION; Material: ARC - M.Ex - Blanc
Pset_MemberCommon - IsExternal: yes; Reference: F.Ri.M_Ext_Rectangulaire_100x100mm
Pset_QuantityTakeOff - Reference: F.Ri.M_Ext_Rectangulaire_100x100mm
Name (Meneau rectangulaire:F.Ri.M_Ext_Rectangulaire_100x100mm:...) | Span (m)
459895 | 0.994779
459896 | 0.994779
459897 | 2.45
459898 | 2.45
459954 | 0.994779
459955 | 0.994779
459956 | 2.45
459957 | 2.45
709815 | 0.994779
709816 | 0.994779
709817 | 2.45
709818 | 2.45
709821 | 0.994779
709822 | 0.994779
709823 | 2.45
709824 | 2.45

# IfcMember: Meneau rectangulaire:F.Ri.M_Ext_Rectangulaire_200x80mm (22)
In: 00_RDC CAF
Type - PredefinedType: MULLION; Material: ARC - M.Ex - Blanc
Pset_MemberCommon - IsExternal: yes; Reference: F.Ri.M_Ext_Rectangulaire_200x80mm; Span: 0.88 m
Pset_QuantityTakeOff - Reference: F.Ri.M_Ext_Rectangulaire_200x80mm
Name (Meneau rectangulaire:F.Ri.M_Ext_Rectangulaire_200x80mm:...)
458559
458583
458593
458604
458615
458626
458637
458648
458659
458670
458681
458692
458703
458726
458737
458748
458759
458770
458781
458792
458803
458814

# IfcMember: Meneau rectangulaire:F.Ri.M_Ext_Rectangulaire_50x30mm (244)
In: 00_RDC CAF
Type - PredefinedType: MULLION; Material: ARC - M.Ex - Blanc
Pset_MemberCommon - IsExternal: yes; Reference: F.Ri.M_Ext_Rectangulaire_50x30mm
Pset_QuantityTakeOff - Reference: F.Ri.M_Ext_Rectangulaire_50x30mm
Name (Meneau rectangulaire:F.Ri.M_Ext_Rectangulaire_50x30mm:...) | Span (m)
458561 | 2.769
458562 | 1.359
458563 | 1.359
458564 | 2.769
458585 | 2.769
458586 | 1.359
458587 | 1.359
458588 | 2.769
458595 | 2.769
458596 | 1.359
458597 | 1.359
458598 | 2.769
458606 | 2.769
458607 | 1.359
458608 | 1.359
458609 | 2.769
458617 | 2.769
458618 | 1.359
458619 | 1.359
458620 | 2.769
458628 | 2.769
458629 | 1.359
458630 | 1.359
458631 | 2.769
458639 | 2.769
458640 | 1.359
458641 | 1.359
458642 | 2.769
458650 | 2.769
458651 | 1.359
458652 | 1.359
458653 | 2.769
458661 | 2.769
458662 | 1.359
458663 | 1.359
458664 | 2.769
458672 | 2.769
458673 | 1.359
458674 | 1.359
458675 | 2.769
458683 | 2.769
458684 | 1.359
458685 | 1.359
458686 | 2.769
458694 | 2.769
458695 | 1.359
458696 | 1.359
458697 | 2.769
458705 | 2.769
458706 | 1.359
458707 | 1.359
458708 | 2.769
458713 | 4.128
458714 | 4.128
458719 | 4.128
458720 | 4.128
458728 | 2.769
458729 | 1.359
458730 | 1.359
458731 | 2.769
458739 | 2.769
458740 | 1.359
458741 | 1.359
458742 | 2.769
458750 | 2.769
458751 | 1.359
458752 | 1.359
458753 | 2.769
458761 | 2.769
458762 | 1.359
458763 | 1.359
458764 | 2.769
458772 | 2.769
458773 | 1.359
458774 | 1.359
458775 | 2.769
458783 | 2.769
458784 | 1.359
458785 | 1.359
458786 | 2.769
458794 | 2.769
458795 | 1.359
458796 | 1.359
458797 | 2.769
458805 | 2.769
458806 | 1.359
458807 | 1.359
458808 | 2.769
458816 | 2.769
458817 | 1.359
458818 | 1.359
458819 | 2.769
459983 | 1.128
459984 | 1.128
459989 | 1.128
459990 | 1.128
459995 | 1.128
459996 | 1.128
460001 | 1.128
460002 | 1.128
460475 | 0.88
460476 | 0.88
460477 | 1.413
460478 | 0.087
460479 | 0.087
460480 | 1.413
460484 | 0.88
460485 | 0.88
460486 | 1.413
460487 | 0.087
460488 | 0.087
460489 | 1.413
460493 | 0.88
460494 | 0.88
460495 | 1.413
460496 | 0.087
460497 | 0.087
460498 | 1.413
460502 | 0.88
460503 | 0.88
460504 | 1.413
460505 | 0.087
460506 | 0.087
460507 | 1.413
460511 | 0.88
460512 | 0.88
460513 | 1.413
460514 | 0.087
460515 | 0.087
460516 | 1.413
460520 | 0.88
460521 | 0.88
460522 | 1.413
460523 | 0.087
460524 | 0.087
460525 | 1.413
460529 | 0.88
460530 | 0.88
460531 | 1.413
460532 | 0.087
460533 | 0.087
460534 | 1.413
460538 | 0.88
460539 | 0.88
460540 | 1.413
460541 | 0.087
460542 | 0.087
460543 | 1.413
460547 | 0.88
460548 | 0.88
460549 | 1.413
460550 | 0.087
460551 | 0.087
460552 | 1.413
460556 | 0.88
460557 | 0.88
460558 | 1.413
460559 | 0.087
460560 | 0.087
460561 | 1.413
460565 | 0.88
460566 | 0.88
460567 | 1.413
460568 | 0.087
460569 | 0.087
460570 | 1.413
460574 | 0.88
460575 | 0.88
460576 | 1.413
460577 | 0.087
460578 | 0.087
460579 | 1.413
460619 | 0.88
460620 | 0.88
460621 | 1.413
460622 | 0.087
460623 | 0.087
460624 | 1.413
460628 | 0.88
460629 | 0.88
460630 | 1.413
460631 | 0.087
460632 | 0.087
460633 | 1.413
460637 | 0.88
460638 | 0.88
460639 | 1.413
460640 | 0.087
460641 | 0.087
460642 | 1.413
460646 | 0.88
460647 | 0.88
460648 | 1.413
460649 | 0.087
460650 | 0.087
460651 | 1.413
460655 | 0.88
460656 | 0.88
460657 | 1.413
460658 | 0.087
460659 | 0.087
460660 | 1.413
460664 | 0.88
460665 | 0.88
460666 | 1.413
460667 | 0.087
460668 | 0.087
460669 | 1.413
460673 | 0.88
460674 | 0.88
460675 | 1.413
460676 | 0.087
460677 | 0.087
460678 | 1.413
460682 | 0.88
460683 | 0.88
460684 | 1.413
460685 | 0.087
460686 | 0.087
460687 | 1.413
460691 | 0.88
460692 | 0.88
460693 | 1.413
460694 | 0.087
460695 | 0.087
460696 | 1.413
460700 | 0.88
460701 | 0.88
460702 | 1.413
460703 | 0.087
460704 | 0.087
460705 | 1.413
460709 | 0.88
460710 | 0.88
460711 | 1.413
460712 | 0.087
460713 | 0.087
460714 | 1.413
460718 | 0.88
460719 | 0.88
460720 | 1.413
460721 | 0.087
460722 | 0.087
460723 | 1.413

# IfcMember: Meneau rectangulaire:F.Ri.M_Ext_Rectangulaire_90x80mm (55)
In: 00_RDC CAF
Type - PredefinedType: MULLION; Material: ARC - M.Ex - Blanc
Pset_MemberCommon - IsExternal: yes; Reference: F.Ri.M_Ext_Rectangulaire_90x80mm; Span: 0.88 m
Pset_QuantityTakeOff - Reference: F.Ri.M_Ext_Rectangulaire_90x80mm
Name (Meneau rectangulaire:F.Ri.M_Ext_Rectangulaire_90x80mm:...)
458560
458578
458584
458594
458599
458605
458610
458616
458621
458627
458632
458638
458643
458649
458654
458660
458665
458671
458676
458682
458687
458693
458698
458704
458709
458712
458715
458718
458721
458727
458732
458738
458743
458749
458754
458760
458765
458771
458776
458782
458787
458793
458798
458804
458809
458815
458820
459982
459985
459988
459991
459994
459997
460000
460003

# IfcMember: Meneau rectangulaire:M.Ri.M_Int_Rectangulaire_115x115mm, Meneau rectangulaire:M.Ri.M_Int_Rectangulaire_115x115mm:459909
In: 00_RDC CAF
Type - PredefinedType: MULLION; Material: ARC - M.In - Blanc
Pset_MemberCommon - IsExternal: no; Reference: M.Ri.M_Int_Rectangulaire_115x115mm; Span: 0.362609 m
Pset_QuantityTakeOff - Reference: M.Ri.M_Int_Rectangulaire_115x115mm

# IfcMember: Meneau rectangulaire:M.Ri.M_Int_Rectangulaire_130x210mm (3)
In: 00_RDC CAF
Type - PredefinedType: MULLION; Material: ARC - M.In - Blanc
Pset_MemberCommon - IsExternal: no; Reference: M.Ri.M_Int_Rectangulaire_130x210mm
Pset_QuantityTakeOff - Reference: M.Ri.M_Int_Rectangulaire_130x210mm
Name (Meneau rectangulaire:M.Ri.M_Int_Rectangulaire_130x210mm:...) | Span (m)
459872 | 1.02
459875 | 1.8589
459878 | 1

# IfcMember: Meneau rectangulaire:M.Ri.M_Int_Rectangulaire_30x115mm (2)
In: 00_RDC CAF
Type - PredefinedType: MULLION; Material: ARC - M.In - Blanc
Pset_MemberCommon - IsExternal: no; Reference: M.Ri.M_Int_Rectangulaire_30x115mm; Span: 2.135 m
Pset_QuantityTakeOff - Reference: M.Ri.M_Int_Rectangulaire_30x115mm
Name (Meneau rectangulaire:M.Ri.M_Int_Rectangulaire_30x115mm:...)
459911
459912

# IfcMember: Meneau rectangulaire:M.Ri.M_Int_Rectangulaire_40x60mm_Avec_Décalage (4)
In: 00_RDC CAF
Type - PredefinedType: MULLION; Material: ARC - M.In - Blanc
Pset_MemberCommon - IsExternal: no; Reference: M.Ri.M_Int_Rectangulaire_40x60mm_Avec_Décalage
Pset_QuantityTakeOff - Reference: M.Ri.M_Int_Rectangulaire_40x60mm_Avec_Décalage
Name (Meneau rectangulaire:M.Ri.M_Int_Rectangulaire_40x60mm_Avec_Décalage:...) | Span (m)
459715 | 0.915
459721 | 1.43781
459752 | 1.07034
459758 | 0.930001

# IfcMember: Meneau rectangulaire:M.Ri.M_Int_Rectangulaire_45x70mm (2)
In: 00_RDC CAF
Type - PredefinedType: MULLION; Material: ARC - M.In - Blanc
Pset_MemberCommon - IsExternal: no; Reference: M.Ri.M_Int_Rectangulaire_45x70mm; Span: 2.19 m
Pset_QuantityTakeOff - Reference: M.Ri.M_Int_Rectangulaire_45x70mm
Name (Meneau rectangulaire:M.Ri.M_Int_Rectangulaire_45x70mm:...)
459883
459884

# IfcMember: Meneau rectangulaire:M.Ri.M_Int_Rectangulaire_55x115mm, Meneau rectangulaire:M.Ri.M_Int_Rectangulaire_55x115mm:459910
In: 00_RDC CAF
Type - PredefinedType: MULLION; Material: ARC - M.In - Blanc
Pset_MemberCommon - IsExternal: no; Reference: M.Ri.M_Int_Rectangulaire_55x115mm; Span: 0.362609 m
Pset_QuantityTakeOff - Reference: M.Ri.M_Int_Rectangulaire_55x115mm

# IfcMember: Meneau rectangulaire:M.Ri.M_Int_Rectangulaire_60x60mm_Avec_Décalage (10)
In: 00_RDC CAF
Type - PredefinedType: MULLION; Material: ARC - M.In - Blanc
Pset_MemberCommon - IsExternal: no; Reference: M.Ri.M_Int_Rectangulaire_60x60mm_Avec_Décalage
Pset_QuantityTakeOff - Reference: M.Ri.M_Int_Rectangulaire_60x60mm_Avec_Décalage
Name (Meneau rectangulaire:M.Ri.M_Int_Rectangulaire_60x60mm_Avec_Décalage:...) | Span (m)
459716 | 1.43781
459717 | 1.9525
459718 | 1.9525
459722 | 0.915
459723 | 1.9525
459753 | 0.930001
459754 | 1.9525
459755 | 1.9525
459759 | 1.07034
459760 | 1.9525

# IfcMember: Meneau rectangulaire:M.Ri.M_Int_Rectangulaire_60x70mm (30)
In: 00_RDC CAF
Type - PredefinedType: MULLION; Material: ARC - M.In - Blanc
Pset_MemberCommon - IsExternal: no; Reference: M.Ri.M_Int_Rectangulaire_60x70mm
Pset_QuantityTakeOff - Reference: M.Ri.M_Int_Rectangulaire_60x70mm
Name (Meneau rectangulaire:M.Ri.M_Int_Rectangulaire_60x70mm:...) | Span (m)
458842 | 0.93
458843 | 2.075
458846 | 1.985
458847 | 0.2
458850 | 0.2
458851 | 0.93
459340 | 0.9
459341 | 2.075
459344 | 1.985
459345 | 0.2
459348 | 0.2
459349 | 0.9
459365 | 0.985
459366 | 2.075
459369 | 1.985
459370 | 0.2
459373 | 0.2
459374 | 0.985
459390 | 0.93
459391 | 2.075
459394 | 1.985
459395 | 0.2
459398 | 0.2
459399 | 0.93
459415 | 0.81
459416 | 2.075
459419 | 1.985
459420 | 0.2
459423 | 0.2
459424 | 0.81

# IfcMember: Meneau rectangulaire:M.Ri.M_Int_Rectangulaire_70x70mm (20)
In: 00_RDC CAF
Type - PredefinedType: MULLION; Material: ARC - M.In - Blanc
Pset_MemberCommon - IsExternal: no; Reference: M.Ri.M_Int_Rectangulaire_70x70mm
Pset_QuantityTakeOff - Reference: M.Ri.M_Int_Rectangulaire_70x70mm
Name (Meneau rectangulaire:M.Ri.M_Int_Rectangulaire_70x70mm:...) | Span (m)
458858 | 0.900818
458859 | 0.890722
458860 | 0.945818
458861 | 0.935722
459356 | 0.900818
459357 | 0.886644
459358 | 0.945818
459359 | 0.931644
459381 | 0.959095
459382 | 1.14918
459383 | 1.00409
459384 | 1.19418
459406 | 0.900579
459407 | 0.890722
459408 | 0.945579
459409 | 0.935722
459431 | 0.905585
459432 | 0.888405
459433 | 0.950585
459434 | 0.933405

# IfcMember: Meneau rectangulaire:M.Ri.M_Int_Rectangulaire_90x70mm (20)
In: 00_RDC CAF
Type - PredefinedType: MULLION; Material: ARC - M.In - Blanc
Pset_MemberCommon - IsExternal: no; Reference: M.Ri.M_Int_Rectangulaire_90x70mm
Pset_QuantityTakeOff - Reference: M.Ri.M_Int_Rectangulaire_90x70mm
Name (Meneau rectangulaire:M.Ri.M_Int_Rectangulaire_90x70mm:...) | Span (m)
458841 | 1.00582
458856 | 0.995722
458857 | 2.02
459336 | 1.04072
459339 | 1.00582
459354 | 0.991644
459355 | 2.02
459361 | 1.03664
459364 | 1.06409
459379 | 1.25418
459380 | 2.02
459386 | 1.29918
459389 | 1.00558
459404 | 0.995722
459405 | 2.02
459411 | 1.04072
459414 | 1.01058
459429 | 0.993405
459430 | 2.02
459436 | 1.03841

# IfcOpeningElement: Opening (38)
In: 00_RDC CAF
Name
Mur de base:M_Ext_Beton_210mm:458536:1 | Pset_OpeningElementCommon - Reference: M_Ext_Beton_210mm; sets with these values: 2
Mur de base:M_Ext_Beton_250mm:458823 | Pset_OpeningElementCommon - Reference: M.Ri_Ext_Grille_RDC_50mm; sets with these values: 2
Mur de base:M_Int_Beton_200mm:458866:1 | Pset_OpeningElementCommon - Reference: M_Int_Beton_200mm; sets with these values: 2
Mur de base:M_Int_Beton_225mm:458867 | Pset_OpeningElementCommon - Reference: P_Int_Simple_Pleine_930x2090mm; sets with these values: 2
Mur de base:Cl_Platre_90mm:459308 | Pset_OpeningElementCommon - Reference: M.Ri_Vitre_40mm_Montant_70X90mm; sets with these values: 2
Mur de base:Cl_Platre_90mm:459360 | Pset_OpeningElementCommon - Reference: M.Ri_Vitre_40mm_Montant_70X90mm; sets with these values: 2
Mur de base:Cl_Platre_100mm:459712 | Pset_OpeningElementCommon - Reference: M.Ri_Vitre_40mm_Montant_50X50mm_Avec_Décalage; sets with these values: 2
Mur de base:Cl_Platre_100mm:459729 | Pset_OpeningElementCommon - Reference: M.Ri_Vitre_40mm_Montant_50X50mm_Avec_Décalage; sets with these values: 2
Mur de base:M_Int_Beton_225mm:460305 | Pset_OpeningElementCommon - Reference: P_Int_Ouverture_Libre_1130x2030mm; sets with these values: 2
Mur de base:M_Ext_Beton_200mm:466061 | Pset_OpeningElementCommon - Reference: M_Ext_Beton_200mm; sets with these values: 2
Mur de base:M_Ext_Beton_200mm:460871:1 | Pset_OpeningElementCommon - Reference: M_Ext_Beton_200mm; sets with these values: 2
Sol:Toiture métallique 74 mm + Isolant PU 40 mm + Etanchéité 16mm:605534 | Pset_OpeningElementCommon - Reference: Toiture métallique 74 mm + Isolant PU 40 mm + Etanchéité 16mm; sets with these values: 2
2 x Mur de base:M_Int_Beton_610mm:709811 | Pset_OpeningElementCommon - Reference: F.Ri._Ext_Vitre_40mm_Montant_100mm; sets with these values: 2
P_Tunnel_Tierce:P_Int_Tierce_Pleine_1380x2000mm:460307:1
P_Tunnel_Tierce:P_Int_Tierce_Pleine_1620x2040mm:459671:1
F_1V:F_Int_1V_Fixe:459016:1
F_1V:F_Int_1V_Fixe:459015:1
F_1V:F_Int_1V_Fixe:459014:1
F_1V:F_Int_1V_Fixe:459013:1
P_Tunnel_Simple:P_Int_Simple_Pleine_930x2090mm:459021:1
2 x Mur de base:M_Int_Beton_200mm:459113
P_Tunnel_Simple:P_Int_Simple_Pleine_700x2060mm:459916:1
P_Tunnel_Simple:P_Int_Simple_Pleine_930x2090mm:459832:1
P_Recouvrement_Simple:P_Int_Simple_Pleine_900x2040mm:459939:1
P_Recouvrement_Simple:P_Int_Simple_Pleine_900x2040mm:459940:1
P_Tunnel_Simple:P_Int_Simple_Pleine_930x1970mm:459452:1
P_Tunnel_Simple:P_Int_Simple_Pleine_930x2040mm:459619:1
Mur de base:Cl_Platre_100mm:459556
P_Recouvrement_Double:P_Int_Double_Pleine_1260x2090mm:459571:1
P_Recouvrement_Double:P_Int_Double_Pleine_1260x2090mm:459572:1
P_Recouvrement_Simple:P_Int_Simple_Pleine_940x2080mm:459569:1
P_Recouvrement_Simple:P_Int_Simple_Pleine_900x2040mm:459945:1
P_Tunnel_Simple:P_Int_Simple_Pleine_950x2090mm:460165:1
P_Tunnel_Double:P_Int_Double_Pleine_1530x2040mm:460415:1
P_Coulissante_Applique:P_Ext_Coulissante_Applique_Pleine_980x2040mm:460972:1
P_Coulissante_Applique_Double:P_Ext_Coulissante_Applique_Double_Vitree_2100x2450mm:709812:1

# IfcPlate: Panneau système:F.Ri.P_Ext_Plein_30mm_Bleu foncé (48)
In: 00_RDC CAF
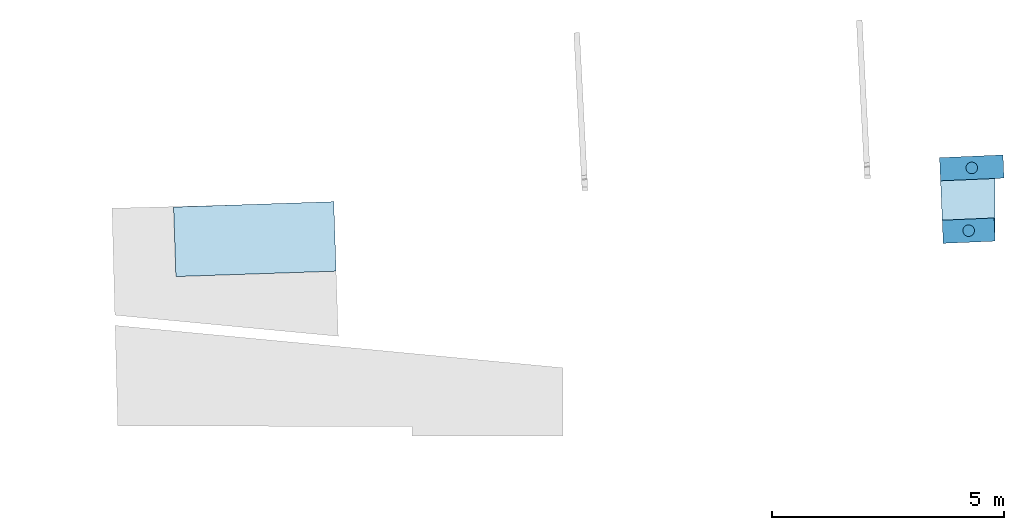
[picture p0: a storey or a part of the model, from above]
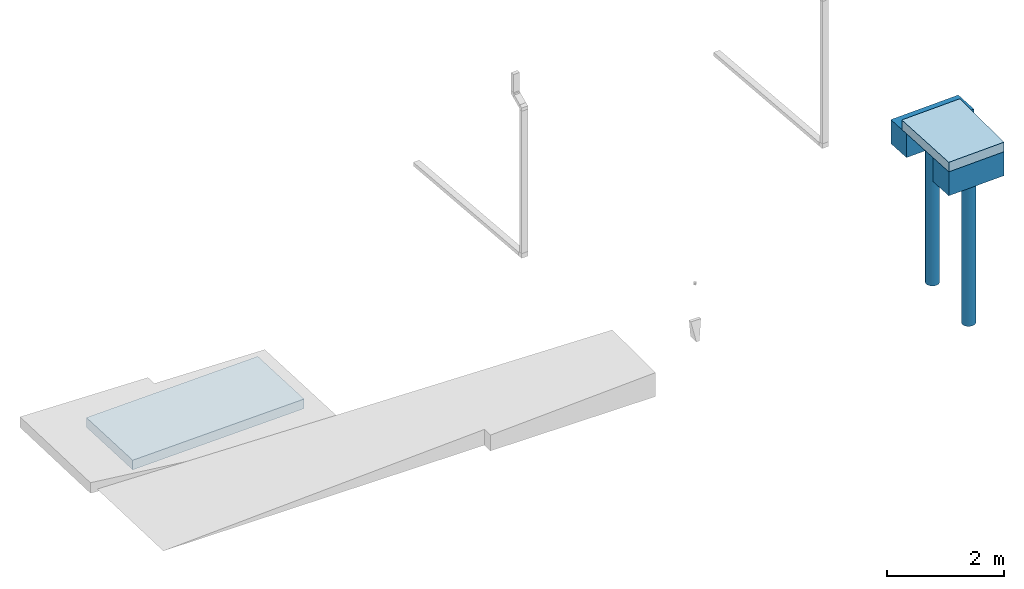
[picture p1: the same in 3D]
Properties of the parts of a building model (IFC2X3), part 2 of 2

# IfcPlate: Panneau système:F.Ri.P_Ext_Plein_30mm_Bleu foncé (48)
Type - PredefinedType: CURTAIN_PANEL; Material: ARC - M.Ex - Bleu Foncé
Pset_PlateCommon - IsExternal: yes; Reference: F.Ri.P_Ext_Plein_30mm_Bleu foncé
Pset_QuantityTakeOff - Reference: F.Ri.P_Ext_Plein_30mm_Bleu foncé
Name (Panneau système:F.Ri.P_Ext_Plein_30mm_Bleu foncé:...)
460473
460580
460482
460581
460491
460582
460500
460583
460509
460584
460518
460585
460527
460586
460536
460587
460545
460588
460554
460589
460563
460590
460572
460591
460617
460724
460626
460725
460635
460726
460644
460727
460653
460728
460662
460729
460671
460730
460680
460731
460689
460732
460698
460733
460707
460734
460716
460735

# IfcPlate: Panneau système:F.Ri.P_Ext_Vitre_30mm (49)
In: 00_RDC CAF
Type - PredefinedType: CURTAIN_PANEL; Material: ARC - M.Ex - Verre
Pset_PlateCommon - IsExternal: yes; Reference: F.Ri.P_Ext_Vitre_30mm
Pset_QuantityTakeOff - Reference: F.Ri.P_Ext_Vitre_30mm
Name (Panneau système:F.Ri.P_Ext_Vitre_30mm:...)
458556
458558
458582
458590
458592
458601
458603
458612
458614
458623
458625
458634
458636
458645
458647
458656
458658
458667
458669
458678
458680
458689
458691
458700
458702
458711
458717
458723
458725
458734
458736
458745
458747
458756
458758
458767
458769
458778
458780
458789
458791
458800
458802
458811
458813
459981
459987
459993
459999

# IfcPlate: Panneau système:F.Ri.P_Ext_Vitre_40mm (4)
In: 00_RDC CAF
Type - PredefinedType: CURTAIN_PANEL; Material: ARC - M.Ex - Verre
Pset_PlateCommon - IsExternal: yes; Reference: F.Ri.P_Ext_Vitre_40mm
Pset_QuantityTakeOff - Reference: F.Ri.P_Ext_Vitre_40mm
Name (Panneau système:F.Ri.P_Ext_Vitre_40mm:...)
459894
459953
709814
709820

# IfcPlate: Panneau système:M.Ri.P_Int_Plein_40mm (5)
In: 00_RDC CAF
Type - PredefinedType: CURTAIN_PANEL; Material: ARC - M.In - Blanc
Type - Pset_PlateCommon - ThermalTransmittance: 3.7021 kg/K/s3
Pset_PlateCommon - IsExternal: no; Reference: M.Ri.P_Int_Plein_40mm
Pset_QuantityTakeOff - Reference: M.Ri.P_Int_Plein_40mm
Name (Panneau système:M.Ri.P_Int_Plein_40mm:...)
458845
459343
459368
459393
459418

# IfcPlate: Panneau système:M.Ri.P_Int_Vitre_40mm (13)
In: 00_RDC CAF
Type - PredefinedType: CURTAIN_PANEL; Material: ARC - M.In - Verre
Type - Pset_PlateCommon - ThermalTransmittance: 6.7069 kg/K/s3
Pset_PlateCommon - IsExternal: no; Reference: M.Ri.P_Int_Vitre_40mm
Pset_QuantityTakeOff - Reference: M.Ri.P_Int_Vitre_40mm
Name (Panneau système:M.Ri.P_Int_Vitre_40mm:...)
458840
458849
459338
459347
459363
459372
459388
459397
459413
459422
459871
459874
459908

# IfcPlate: Panneau système:M.Ri.P_Int_Vitre_40mm_Avec_Décalage (2)
In: 00_RDC CAF
Type - PredefinedType: CURTAIN_PANEL; Material: ARC - M.In - Verre
Pset_PlateCommon - IsExternal: no; Reference: M.Ri.P_Int_Vitre_40mm_Avec_Décalage
Pset_QuantityTakeOff - Reference: M.Ri.P_Int_Vitre_40mm_Avec_Décalage
Name (Panneau système:M.Ri.P_Int_Vitre_40mm_Avec_Décalage:...)
459714
459751

# IfcRailing: Garde-corps:CLO_2_traverse_100x20_1450mm, Garde-corps:CLO_2_traverse_100x20_1450mm:461098
In: 00_RDC CAF
Material: STR - Acier, <Unnamed>, ARC - Metal
Pset_QuantityTakeOff - Reference: CLO_2_traverse_100x20_1450mm
Pset_RailingCommon - IsExternal: no; Reference: CLO_2_traverse_100x20_1450mm; Height: 1.45 m

# IfcRailing: Garde-corps:CLO_2_traverse_100x20_1480mm, Garde-corps:CLO_2_traverse_100x20_1480mm:570752
In: 00_RDC CAF
Material: STR - Acier, <Unnamed>, ARC - Metal
Pset_QuantityTakeOff - Reference: CLO_2_traverse_100x20_1480mm
Pset_RailingCommon - IsExternal: no; Reference: CLO_2_traverse_100x20_1480mm; Height: 1.48 m

# IfcRailing: Garde-corps:CLO_2_traverse_100x20_1610mm (2)
In: 00_RDC CAF
Material: STR - Acier, <Unnamed>, ARC - Metal
Pset_QuantityTakeOff - Reference: CLO_2_traverse_100x20_1610mm
Pset_RailingCommon - IsExternal: no; Reference: CLO_2_traverse_100x20_1610mm; Height: 1.61 m
Name (Garde-corps:CLO_2_traverse_100x20_1610mm:...)
461037
461155

# IfcRailing: Garde-corps:GC_1_lisse_40x30+Plein_800mm, Garde-corps:GC_1_lisse_40x30+Plein_800mm:558775
In: 00_RDC CAF
Material: STR - Acier, ARC - Metal
Pset_QuantityTakeOff - Reference: GC_1_lisse_40x30+Plein_800mm
Pset_RailingCommon - IsExternal: no; Reference: GC_1_lisse_40x30+Plein_800mm; Height: 0.75 m

# IfcRailing: Garde-corps:GC_1_lisse_40x30+Plein_900mm (3)
In: 00_RDC CAF
Material: STR - Acier, ARC - Metal
Pset_QuantityTakeOff - Reference: GC_1_lisse_40x30+Plein_900mm
Pset_RailingCommon - IsExternal: no; Reference: GC_1_lisse_40x30+Plein_900mm; Height: 0.9 m
Name (Garde-corps:GC_1_lisse_40x30+Plein_900mm:...)
459496
459523
459543

# IfcRailing: Garde-corps:GC_1_lisse_D50_950mm (5)
In: 00_RDC CAF
Material: STR - Acier, ARC - Metal
Pset_QuantityTakeOff - Reference: GC_1_lisse_D50_950mm
Pset_RailingCommon - IsExternal: no; Reference: GC_1_lisse_D50_950mm; Height: 0.95 m
Name (Garde-corps:GC_1_lisse_D50_950mm:...)
461188
461225
461261
461283
461306

# IfcRailing: Garde-corps:GC_1_lisse_D50_950mm 2 (4)
In: 00_RDC CAF
Material: ARC - Metal
Pset_QuantityTakeOff - Reference: GC_1_lisse_D50_950mm 2
Pset_RailingCommon - IsExternal: no; Reference: GC_1_lisse_D50_950mm 2; Height: 0.95 m
Name (Garde-corps:GC_1_lisse_D50_950mm 2:...)
461325
461346
461364
461388

# IfcRailing: Garde-corps:GC_2_lisses_D25_550mm, Garde-corps:GC_2_lisses_D25_550mm:460423
In: 00_RDC CAF
Material: STR - Acier
Pset_QuantityTakeOff - Reference: GC_2_lisses_D25_550mm
Pset_RailingCommon - IsExternal: no; Reference: GC_2_lisses_D25_550mm; Height: 0.8 m

# IfcRailing: Garde-corps:GC_Main courante_au_mur_1_lisse_40x30 (3)
In: 00_RDC CAF
Material: ARC - Metal
Pset_QuantityTakeOff - Reference: GC_Main courante_au_mur_1_lisse_40x30
Pset_RailingCommon - IsExternal: no; Reference: GC_Main courante_au_mur_1_lisse_40x30; Height: 0.9 m
Name (Garde-corps:GC_Main courante_au_mur_1_lisse_40x30:...)
459622
459639
459655

# IfcRailing: Garde-corps:GC_Main_courante_au_mur, Garde-corps:GC_Main_courante_au_mur:460323
In: 00_RDC CAF
Material: <Unnamed>
Pset_QuantityTakeOff - Reference: GC_Main_courante_au_mur
Pset_RailingCommon - IsExternal: no; Reference: GC_Main_courante_au_mur; Height: 0.9 m

# IfcRamp: Rampe d'accès:Ra_Acces_700mm_Plein (2)
In: Fondations
Material: ARC - Béton
Pset_QuantityTakeOff - Reference: Ra_Acces_700mm_Plein
Pset_RampCommon - IsExternal: yes; Reference: Ra_Acces_700mm_Plein
Name (Rampe d'accès:Ra_Acces_700mm_Plein:...)
460748
460773

# IfcRoof: Toit de base:Co_Plafond_Entrée_280mm, Toit de base:Co_Plafond_Entrée_280mm:459975
In: 00_RDC CAF
Material: STR - Beton Mur 0.28 m
Pset_QuantityTakeOff - Reference: Co_Plafond_Entrée_280mm
Pset_RoofCommon - IsExternal: yes; Reference: Co_Plafond_Entrée_280mm; ProjectedArea: 0.000291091 m2; TotalArea: 3.91121 m2

# IfcRoof: Toit de base:Co_Plafond_Entrée_550mm, Toit de base:Co_Plafond_Entrée_550mm:459902
In: 00_RDC CAF
Material: STR - Beton Mur 0.55 m
Pset_QuantityTakeOff - Reference: Co_Plafond_Entrée_550mm
Pset_RoofCommon - IsExternal: yes; Reference: Co_Plafond_Entrée_550mm; ProjectedArea: 15.9234 m2; TotalArea: 15.9234 m2

# IfcSlab: Casque de battage-1 poteau:TP 1120x500x500 - Pieux 250, Casque de battage-1 poteau:TP 1120x500x500 - Pieux 250:835862
In: Fondations
Type - PredefinedType: BASESLAB; Material: Béton - Béton coulé sur place
Classification: A1010130 Pile Caps (Uniformat)
Pset_QuantityTakeOff - Reference: TP 1120x500x500 - Pieux 250; sets with these values: 2
Pset_SlabCommon - IsExternal: no; PitchAngle: 0 deg; Reference: TP 1120x500x500 - Pieux 250

# IfcSlab: Casque de battage-1 poteau:TP 500x500x500 - Pieux 250 (12)
In: 00_RDC CAF
Type - PredefinedType: BASESLAB; Material: Béton - Béton coulé sur place
Classification: A1010130 Pile Caps (Uniformat)
Pset_QuantityTakeOff - Reference: TP 500x500x500 - Pieux 250; sets with these values: 2
Pset_SlabCommon - IsExternal: no; Reference: TP 500x500x500 - Pieux 250
Name (Casque de battage-1 poteau:TP 500x500x500 - Pieux 250:...)
638901
643688
643859
644102
645346
645585
656163
656200
656273
656275
694135
702298

# IfcSlab: Casque de battage-1 poteau:TP1370x500x500 - Pieux 250, Casque de battage-1 poteau:TP1370x500x500 - Pieux 250:655863
In: Fondations
Type - PredefinedType: BASESLAB; Material: Béton - Béton coulé sur place
Classification: A1010130 Pile Caps (Uniformat)
Pset_QuantityTakeOff - Reference: TP1370x500x500 - Pieux 250; sets with these values: 2
Pset_SlabCommon - IsExternal: no; Reference: TP1370x500x500 - Pieux 250

# IfcSlab: Palier monobloc:S_Beton_200 mm, Escalier coulé sur place:Escalier:460808 Landing 1
In: 00_RDC CAF
Type - PredefinedType: LANDING
Material: STR - Beton
Pset_QuantityTakeOff - Reference: S_Beton_200 mm; sets with these values: 2
Pset_SlabCommon - IsExternal: no; PitchAngle: 0 deg; Reference: S_Beton_200 mm

# IfcSlab: Palier non-monobloc:Palier non-monobloc (2)
In: 00_RDC CAF
Type - PredefinedType: LANDING
Material: STR - Beton
Pset_QuantityTakeOff - Reference: Palier non-monobloc; sets with these values: 2
Pset_SlabCommon - IsExternal: no; Reference: Palier non-monobloc
Name (Escalier assemblé:Escalier:...)
459485 Landing 1
459485 Landing 2

# IfcSlab: Pieu-Conduite en acier:Diamètre de 250 mm (14)
Type - PredefinedType: BASESLAB
Classification: A1020130 Piles - Steel Pipe (Uniformat)
Pset_QuantityTakeOff - Reference: Diamètre de 250 mm; sets with these values: 2
Pset_SlabCommon - IsExternal: no; Reference: Diamètre de 250 mm
Name (Pieu-Conduite en acier:Diamètre de 250 mm:...) | In
638902 | 00_RDC CAF
643689 | 00_RDC CAF
643860 | 00_RDC CAF
644103 | 00_RDC CAF
645347 | 00_RDC CAF
645586 | 00_RDC CAF
655864 | Fondations
656164 | 00_RDC CAF
656201 | 00_RDC CAF
656274 | 00_RDC CAF
656276 | 00_RDC CAF
694136 | 00_RDC CAF
702299 | 00_RDC CAF
835863 | Fondations

# IfcSlab: Sol:A_Plancher_Estrade_16mm (2)
In: 00_RDC CAF
Type - PredefinedType: FLOOR; Material: ARC - Estrade 0.16 m
Pset_QuantityTakeOff - Reference: A_Plancher_Estrade_16mm; sets with these values: 2
Pset_SlabCommon - IsExternal: no; LoadBearing: no; PitchAngle: 0 deg; Reference: A_Plancher_Estrade_16mm
Name (Sol:A_Plancher_Estrade_16mm:...)
460140
460153

# IfcSlab: Sol:S_Beton_300 mm, Sol:S_Beton_300 mm:460246
In: 00_RDC CAF
Type - PredefinedType: FLOOR; Material: STR - Beton 0.3 m
Pset_QuantityTakeOff - Reference: S_Beton_300 mm; sets with these values: 2
Pset_SlabCommon - LoadBearing: yes; IsExternal: no; PitchAngle: 0 deg; Reference: S_Beton_300 mm

# IfcSlab: Sol:S_Beton_Bac acier_200+120 mm Variable (3)
In: 00_RDC CAF
Type - PredefinedType: FLOOR; Material: STR - Beton 0.32 m
Pset_QuantityTakeOff - Reference: S_Beton_Bac acier_200+120 mm Variable; sets with these values: 2
Pset_SlabCommon - IsExternal: no; Reference: S_Beton_Bac acier_200+120 mm Variable; PitchAngle: 0 deg
Name (Sol:S_Beton_Bac acier_200+120 mm Variable:...) | LoadBearing
458827 | yes
460310 | no
460408 | yes

# IfcSlab: Sol:S_Caillebotis_50 mm, Sol:S_Caillebotis_50 mm:460738
In: 00_RDC CAF
Type - PredefinedType: FLOOR; Material: STR - Caillebotis 0.05 m
Pset_QuantityTakeOff - Reference: S_Caillebotis_50 mm; sets with these values: 2
Pset_SlabCommon - IsExternal: yes; LoadBearing: no; PitchAngle: 0 deg; Reference: S_Caillebotis_50 mm

# IfcSlab: Sol:S_Sol_vegetalise_200 mm (6)
In: 00_RDC CAF
Type - PredefinedType: FLOOR; Material: SITE - Herbe 0.2 m
Pset_QuantityTakeOff - Reference: S_Sol_vegetalise_200 mm; sets with these values: 2
Pset_SlabCommon - IsExternal: no; LoadBearing: no; Reference: S_Sol_vegetalise_200 mm
Name (Sol:S_Sol_vegetalise_200 mm:...) | PitchAngle (deg)
460975 | 0
460987 | 0
561523 | 0
687014 | 1.7756
687527 | 1.7756
687960 | 1.7756

# IfcSlab: Sol:Toiture métallique 74 mm + Isolant PU 40 mm + Etanchéité 16mm, Sol:Toiture métallique 74 mm + Isolant PU 40 mm + Etanchéité 16mm:680005
In: 00_RDC CAF
Type - PredefinedType: FLOOR; Material: Asphalte, bitume 0.016 m, Isolant imperméable 0.039 m, Platelage métallique 0.075 m
Type - Pset_SlabCommon - ThermalTransmittance: 20.205 kg/K/s3
Pset_QuantityTakeOff - Reference: Toiture métallique 74 mm + Isolant PU 40 mm + Etanchéité 16mm; sets with these values: 2
Pset_SlabCommon - LoadBearing: yes; IsExternal: no; Reference: Toiture métallique 74 mm + Isolant PU 40 mm + Etanchéité 16mm; PitchAngle: 1.7756 deg

# IfcSlab: Sol:Vo_Dalle_Beton_150mm (3)
In: 00_RDC CAF
Type - PredefinedType: FLOOR; Material: STR - Beton 0.15 m, Terre 0.15 m
Type - Pset_SlabCommon - ThermalTransmittance: 5.58 kg/K/s3
Pset_QuantityTakeOff - Reference: Vo_Dalle_Beton_150mm; sets with these values: 2
Pset_SlabCommon - LoadBearing: yes; IsExternal: no; PitchAngle: 0 deg; Reference: Vo_Dalle_Beton_150mm
Name (Sol:Vo_Dalle_Beton_150mm:...)
460797
619892
620913

# IfcSlab: Sol:Vo_Dalle_Beton_200mm (4)
Type - PredefinedType: FLOOR; Material: STR - Beton 0.2 m
Pset_QuantityTakeOff - Reference: Vo_Dalle_Beton_200mm; sets with these values: 2
Pset_SlabCommon - LoadBearing: yes; IsExternal: no; PitchAngle: 0 deg; Reference: Vo_Dalle_Beton_200mm
Name (Sol:Vo_Dalle_Beton_200mm:...) | In
460782 | 00_RDC CAF
636626 | 00_RDC CAF
655340 | Fondations
655882 | Fondations

# IfcSlab: Toit de base:Co_Plafond_Entrée_550mm, Toit de base:Co_Plafond_Entrée_550mm:459902
In: 00_RDC CAF
PredefinedType: ROOF; Material: STR - Beton Mur 0.55 m
Pset_QuantityTakeOff - Reference: Co_Plafond_Entrée_550mm; sets with these values: 2
Pset_SlabCommon - IsExternal: yes; PitchAngle: 0 deg; Reference: Co_Plafond_Entrée_550mm

# IfcStair: Escalier assemblé:E_Escalier_Assemble_Béton 2, Escalier assemblé:Escalier:459485
In: 00_RDC CAF
Pset_QuantityTakeOff - Reference: E_Escalier_Assemble_Béton 2
Pset_StairCommon - IsExternal: no; Reference: E_Escalier_Assemble_Béton 2; NumberOfRiser: 26; NumberOfTreads: 26; RiserHeight: 0.176077 m; TreadLength: 0.29 m

# IfcStair: Escalier coulé sur place:E_Coule_en_place_Beton_Paillasse_550mm (6)
In: 00_RDC CAF
ShapeType: STRAIGHT_RUN_STAIR
Pset_QuantityTakeOff - Reference: E_Coule_en_place_Beton_Paillasse_550mm
Pset_StairCommon - IsExternal: no; Reference: E_Coule_en_place_Beton_Paillasse_550mm
Name (Escalier coulé sur place:Escalier:...) | NumberOfRiser | NumberOfTreads | RiserHeight (m) | TreadLength (m)
460320 | 4 | 4 | 0.1375 | 0.28
460342 | 4 | 4 | 0.1375 | 0.28
460420 | 4 | 4 | 0.165 | 0.29
460808 | 3 | 2 | 0.166667 | 0.3
697161 | 4 | 3 | 0.17375 | 0.28
699063 | 4 | 3 | 0.17375 | 0.28

# IfcStairFlight: Volée monobloc:E_Beton_550 mm (5)
In: 00_RDC CAF
Material: <Unnamed>
Pset_QuantityTakeOff - Reference: E_Beton_550 mm
Pset_StairFlightCommon - Reference: E_Beton_550 mm; NosingLength: 0 m
Name (Escalier coulé sur place:Escalier:...) | NumberOfRiser = Pset_StairFlightCommon, NumberOfRiser | NumberOfTreads = Pset_StairFlightCommon, NumberOfTreads | RiserHeight (m) | TreadLength (m) | Pset_StairFlightCommon, RiserHeight (m) | Pset_StairFlightCommon, TreadLength (m) = TreadLengthAtOffset (m) = TreadLengthAtInnerSide (m)
460320 Run 1 | 4 | 4 | 0.451115 | 0.918635 | 0.1375 | 0.28
460342 Run 1 | 4 | 4 | 0.451115 | 0.918635 | 0.1375 | 0.28
460808 Run 1 | 3 | 2 | 0.546807 | 0.984252 | 0.166667 | 0.3
697161 Run 1 | 4 | 3 | 0.570046 | 0.918635 | 0.17375 | 0.28
699063 Run 1 | 4 | 3 | 0.570046 | 0.918635 | 0.17375 | 0.28

# IfcStairFlight: Volée monobloc:E_Beton_550 mm, Escalier coulé sur place:Escalier:460420 Run 1
In: 00_RDC CAF
Type - PredefinedType: STRAIGHT
NumberOfRiser: 4; NumberOfTreads: 4; RiserHeight: 0.541339 m; TreadLength: 0.951444 m; Material: <Unnamed>
Pset_QuantityTakeOff - Reference: E_Beton_550 mm
Pset_StairFlightCommon - Reference: E_Beton_550 mm; NosingLength: 0 m; NumberOfRiser: 4; NumberOfTreads: 4; RiserHeight: 0.165 m; TreadLength: 0.29 m; WalkingLineOffset: 4.03665 m; TreadLengthAtOffset: 0.29 m; TreadLengthAtInnerSide: 0.29 m

# IfcStairFlight: Volée non-monobloc:Béton_Marche 50 mm avec Contremarche + nez 30mm 2 (3)
In: 00_RDC CAF
Type - PredefinedType: STRAIGHT
RiserHeight: 0.57768 m; TreadLength: 0.951444 m; Material: STR - Beton
Pset_QuantityTakeOff - Reference: Béton_Marche 50 mm avec Contremarche + nez 30mm 2
Pset_StairFlightCommon - Reference: Béton_Marche 50 mm avec Contremarche + nez 30mm 2; RiserHeight: 0.176077 m; TreadLength: 0.29 m; NosingLength: 0.02 m; WalkingLineOffset: 2.95276 m; TreadLengthAtOffset: 0.29 m; TreadLengthAtInnerSide: 0.29 m
Name (Escalier assemblé:Escalier:...) | NumberOfRiser = NumberOfTreads = Pset_StairFlightCommon, NumberOfRiser = Pset_StairFlightCommon, NumberOfTreads
459485 Run 1 | 11
459485 Run 2 | 7
459485 Run 3 | 8

# IfcWall: Mur de base:Cl_Platre_100mm, Mur de base:Cl_Platre_100mm:459869
In: 00_RDC CAF
Type - PredefinedType: STANDARD; Material: ARC - Cloison 0.1 m
Type - Pset_ReinforcementBarPitchOfWall - Description: Cloison
Pset_QuantityTakeOff - Reference: Cl_Platre_100mm; sets with these values: 2
Pset_WallCommon - ExtendToStructure: no; IsExternal: no; LoadBearing: no; Reference: Cl_Platre_100mm

# IfcWall: Mur de base:Cl_Platre_90mm (3)
In: 00_RDC CAF
Type - PredefinedType: STANDARD; Material: ARC - Cloison 0.09 m
Type - Pset_ReinforcementBarPitchOfWall - Description: Cloison
Pset_QuantityTakeOff - Reference: Cl_Platre_90mm; sets with these values: 2
Pset_WallCommon - ExtendToStructure: no; IsExternal: no; LoadBearing: no; Reference: Cl_Platre_90mm
Name (Mur de base:Cl_Platre_90mm:...)
459385
459410
459435

# IfcWall: Mur de base:M_Ext_Beton_200mm, Mur de base:M_Ext_Beton_200mm:460444
In: 00_RDC CAF
Type - PredefinedType: STANDARD; Material: STR - Beton Mur 0.2 m
Type - Pset_ReinforcementBarPitchOfWall - Description: Mur beton
Pset_QuantityTakeOff - Reference: M_Ext_Beton_200mm; sets with these values: 2
Pset_WallCommon - IsExternal: yes; ExtendToStructure: no; LoadBearing: yes; Reference: M_Ext_Beton_200mm

# IfcWall: Mur de base:M_Ext_Beton_210mm (2)
In: 00_RDC CAF
Type - PredefinedType: STANDARD; Material: STR - Beton Mur 0.21 m
Type - Pset_ReinforcementBarPitchOfWall - Description: Mur beton
Pset_QuantityTakeOff - Reference: M_Ext_Beton_210mm; sets with these values: 2
Pset_WallCommon - IsExternal: yes; ExtendToStructure: no; LoadBearing: yes; Reference: M_Ext_Beton_210mm
Name (Mur de base:M_Ext_Beton_210mm:...)
458534
459890

# IfcWall: Mur de base:M_Ext_Beton_280mm, Mur de base:M_Ext_Beton_280mm:460446
In: 00_RDC CAF
Type - PredefinedType: STANDARD; Material: STR - Beton Mur 0.28 m
Type - Pset_ReinforcementBarPitchOfWall - Description: Mur beton
Pset_QuantityTakeOff - Reference: M_Ext_Beton_280mm; sets with these values: 2
Pset_WallCommon - IsExternal: yes; ExtendToStructure: no; LoadBearing: yes; Reference: M_Ext_Beton_280mm

# IfcWall: Mur de base:M_Ext_Beton_420mm, Mur de base:M_Ext_Beton_420mm:458824
In: 00_RDC CAF
Type - PredefinedType: STANDARD; Material: STR - Beton Mur 0.42 m
Type - Pset_ReinforcementBarPitchOfWall - Description: Mur beton
Pset_QuantityTakeOff - Reference: M_Ext_Beton_420mm; sets with these values: 2
Pset_WallCommon - IsExternal: yes; ExtendToStructure: no; LoadBearing: yes; Reference: M_Ext_Beton_420mm

# IfcWall: Mur de base:M_Int_Beton_180mm (2)
In: 00_RDC CAF
Type - PredefinedType: STANDARD; Material: STR - Beton Mur 0.18 m
Type - Pset_ReinforcementBarPitchOfWall - Description: Mur beton
Pset_QuantityTakeOff - Reference: M_Int_Beton_180mm; sets with these values: 2
Pset_WallCommon - ExtendToStructure: no; IsExternal: no; LoadBearing: no; Reference: M_Int_Beton_180mm
Name (Mur de base:M_Int_Beton_180mm:...)
459307
459865

# IfcWall: Mur de base:M_Int_Beton_200mm, Mur de base:M_Int_Beton_200mm:458865
In: 00_RDC CAF
Type - PredefinedType: STANDARD; Material: STR - Beton Mur 0.2 m
Type - Pset_ReinforcementBarPitchOfWall - Description: Mur beton
Pset_QuantityTakeOff - Reference: M_Int_Beton_200mm; sets with these values: 2
Pset_WallCommon - ExtendToStructure: no; IsExternal: no; LoadBearing: no; Reference: M_Int_Beton_200mm

# IfcWall: Mur de base:M_Int_Beton_210mm, Mur de base:M_Int_Beton_210mm:459451
In: 00_RDC CAF
Type - PredefinedType: STANDARD; Material: STR - Beton Mur 0.21 m
Type - Pset_ReinforcementBarPitchOfWall - Description: Mur beton
Pset_QuantityTakeOff - Reference: M_Int_Beton_210mm; sets with these values: 2
Pset_WallCommon - ExtendToStructure: no; IsExternal: no; LoadBearing: no; Reference: M_Int_Beton_210mm

# IfcWall: Mur de base:M_Int_Beton_480mm, Mur de base:M_Int_Beton_480mm:459918
In: 00_RDC CAF
Type - PredefinedType: STANDARD; Material: STR - Beton Mur 0.48 m
Type - Pset_ReinforcementBarPitchOfWall - Description: Mur beton
Pset_QuantityTakeOff - Reference: M_Int_Beton_480mm; sets with these values: 2
Pset_WallCommon - ExtendToStructure: no; IsExternal: no; LoadBearing: no; Reference: M_Int_Beton_480mm

# IfcWall: Mur de base:M_Int_Beton_660mm, Mur de base:M_Int_Beton_660mm:459889
In: 00_RDC CAF
Type - PredefinedType: STANDARD; Material: STR - Beton Mur 0.66 m
Type - Pset_ReinforcementBarPitchOfWall - Description: Mur beton
Pset_QuantityTakeOff - Reference: M_Int_Beton_660mm; sets with these values: 2
Pset_WallCommon - ExtendToStructure: no; IsExternal: no; LoadBearing: no; Reference: M_Int_Beton_660mm

# IfcWallStandardCase: Mur de base:Cl_Bois_25mm (7)
In: 00_RDC CAF
Type - PredefinedType: STANDARD; Material: ARC - Cloison 0.025 m
Type - Pset_ReinforcementBarPitchOfWall - Description: Cloison
Pset_QuantityTakeOff - Reference: Cl_Bois_25mm; sets with these values: 2
Pset_WallCommon - ExtendToStructure: no; IsExternal: no; LoadBearing: no; Reference: Cl_Bois_25mm
Name (Mur de base:Cl_Bois_25mm:...)
460129
460130
460131
460132
460133
460134
460135

# IfcWallStandardCase: Mur de base:Cl_Platre_100mm (18)
In: 00_RDC CAF
Type - PredefinedType: STANDARD; Material: ARC - Cloison 0.1 m
Type - Pset_ReinforcementBarPitchOfWall - Description: Cloison
Pset_QuantityTakeOff - Reference: Cl_Platre_100mm; sets with these values: 2
Pset_WallCommon - IsExternal: no; LoadBearing: no; Reference: Cl_Platre_100mm
Name (Mur de base:Cl_Platre_100mm:...) | ExtendToStructure
458538 | yes
458837 | no
458838 | no
459011 | no
459012 | no
459017 | no
459018 | no
459019 | no
459020 | no
459448 | no
459518 | no
459556 | no
459567 | no
459712 | no
459727 | no
459729 | no
459731 | no
459860 | no

# IfcWallStandardCase: Mur de base:Cl_Platre_110mm (7)
In: 00_RDC CAF
Type - PredefinedType: STANDARD; Material: ARC - Cloison 0.11 m
Type - Pset_ReinforcementBarPitchOfWall - Description: Cloison
Pset_QuantityTakeOff - Reference: Cl_Platre_110mm; sets with these values: 2
Pset_WallCommon - ExtendToStructure: no; IsExternal: no; LoadBearing: no; Reference: Cl_Platre_110mm
Name (Mur de base:Cl_Platre_110mm:...)
458862
458864
459449
459450
459453
459455
460164

# IfcWallStandardCase: Mur de base:Cl_Platre_160mm (5)
In: 00_RDC CAF
Type - PredefinedType: STANDARD; Material: ARC - Cloison 0.16 m
Type - Pset_ReinforcementBarPitchOfWall - Description: Cloison
Pset_QuantityTakeOff - Reference: Cl_Platre_160mm; sets with these values: 2
Pset_WallCommon - IsExternal: no; LoadBearing: no; Reference: Cl_Platre_160mm
Name (Mur de base:Cl_Platre_160mm:...) | ExtendToStructure
460026 | yes
460027 | yes
460028 | yes
460029 | yes
460302 | no

# IfcWallStandardCase: Mur de base:Cl_Platre_50mm_Gaine (6)
In: 00_RDC CAF
Type - PredefinedType: STANDARD; Material: ARC - Cloison 0.05 m
Type - Pset_ReinforcementBarPitchOfWall - Description: Cloison
Pset_QuantityTakeOff - Reference: Cl_Platre_50mm_Gaine; sets with these values: 2
Pset_WallCommon - ExtendToStructure: no; IsExternal: no; LoadBearing: no; Reference: Cl_Platre_50mm_Gaine
Name (Mur de base:Cl_Platre_50mm_Gaine:...)
459797
459798
459799
459800
459801
459861

# IfcWallStandardCase: Mur de base:Cl_Platre_60mm (3)
In: 00_RDC CAF
Type - PredefinedType: STANDARD; Material: ARC - Cloison 0.06 m
Type - Pset_ReinforcementBarPitchOfWall - Description: Cloison
Pset_QuantityTakeOff - Reference: Cl_Platre_60mm; sets with these values: 2
Pset_WallCommon - ExtendToStructure: no; IsExternal: no; LoadBearing: no; Reference: Cl_Platre_60mm
Name (Mur de base:Cl_Platre_60mm:...)
459566
459570
459859

# IfcWallStandardCase: Mur de base:Cl_Platre_80mm (4)
In: 00_RDC CAF
Type - PredefinedType: STANDARD; Material: ARC - Cloison 0.08 m
Type - Pset_ReinforcementBarPitchOfWall - Description: Cloison
Pset_QuantityTakeOff - Reference: Cl_Platre_80mm; sets with these values: 2
Pset_WallCommon - ExtendToStructure: no; IsExternal: no; LoadBearing: no; Reference: Cl_Platre_80mm
Name (Mur de base:Cl_Platre_80mm:...)
459305
459459
459519
460209

# IfcWallStandardCase: Mur de base:Cl_Platre_90mm (2)
In: 00_RDC CAF
Type - PredefinedType: STANDARD; Material: ARC - Cloison 0.09 m
Type - Pset_ReinforcementBarPitchOfWall - Description: Cloison
Pset_QuantityTakeOff - Reference: Cl_Platre_90mm; sets with these values: 2
Pset_WallCommon - ExtendToStructure: no; IsExternal: no; LoadBearing: no; Reference: Cl_Platre_90mm
Name (Mur de base:Cl_Platre_90mm:...)
459308
459360

# IfcWallStandardCase: Mur de base:Cl_Sepration_80mm (8)
In: 00_RDC CAF
Type - PredefinedType: STANDARD; Material: ARC - Cloison 0.08 m
Type - Pset_ReinforcementBarPitchOfWall - Description: Cloison
Pset_QuantityTakeOff - Reference: Cl_Sepration_80mm; sets with these values: 2
Pset_WallCommon - ExtendToStructure: no; IsExternal: no; LoadBearing: no; Reference: Cl_Sepration_80mm
Name (Mur de base:Cl_Sepration_80mm:...)
459437
459438
459439
459440
459456
459457
459458
460166

# IfcWallStandardCase: Mur de base:M_Ext_Beton_150mm (2)
In: 00_RDC CAF
Type - PredefinedType: STANDARD; Material: STR - Beton Mur 0.15 m
Type - Pset_ReinforcementBarPitchOfWall - Description: Mur beton
Pset_QuantityTakeOff - Reference: M_Ext_Beton_150mm; sets with these values: 2
Pset_WallCommon - IsExternal: yes; ExtendToStructure: no; LoadBearing: yes; Reference: M_Ext_Beton_150mm
Name (Mur de base:M_Ext_Beton_150mm:...)
459314
459315

# IfcWallStandardCase: Mur de base:M_Ext_Beton_200mm (18)
In: 00_RDC CAF
Type - PredefinedType: STANDARD; Material: STR - Beton Mur 0.2 m
Type - Pset_ReinforcementBarPitchOfWall - Description: Mur beton
Pset_QuantityTakeOff - Reference: M_Ext_Beton_200mm; sets with these values: 2
Pset_WallCommon - IsExternal: yes; ExtendToStructure: no; LoadBearing: yes; Reference: M_Ext_Beton_200mm
Name (Mur de base:M_Ext_Beton_200mm:...)
460442
460443
460445
460451
460452
460453
460454
460456
460457
460458
460592
460871
460872
460908
460909
561426
561674
835340

# IfcWallStandardCase: Mur de base:M_Ext_Beton_210mm, Mur de base:M_Ext_Beton_210mm:458536
In: 00_RDC CAF
Type - PredefinedType: STANDARD; Material: STR - Beton Mur 0.21 m
Type - Pset_ReinforcementBarPitchOfWall - Description: Mur beton
Pset_QuantityTakeOff - Reference: M_Ext_Beton_210mm; sets with these values: 2
Pset_WallCommon - IsExternal: yes; ExtendToStructure: no; LoadBearing: yes; Reference: M_Ext_Beton_210mm

# IfcWallStandardCase: Mur de base:M_Ext_Beton_220mm (3)
In: 00_RDC CAF
Type - PredefinedType: STANDARD; Material: STR - Beton Mur 0.22 m
Type - Pset_ReinforcementBarPitchOfWall - Description: Mur beton
Pset_QuantityTakeOff - Reference: M_Ext_Beton_220mm; sets with these values: 2
Pset_WallCommon - IsExternal: yes; ExtendToStructure: no; LoadBearing: yes; Reference: M_Ext_Beton_220mm
Name (Mur de base:M_Ext_Beton_220mm:...)
460602
460744
460745

# IfcWallStandardCase: Mur de base:M_Ext_Beton_230mm, Mur de base:M_Ext_Beton_230mm:460255
In: 00_RDC CAF
Type - PredefinedType: STANDARD; Material: STR - Beton Mur 0.23 m
Type - Pset_ReinforcementBarPitchOfWall - Description: Mur beton
Pset_QuantityTakeOff - Reference: M_Ext_Beton_230mm; sets with these values: 2
Pset_WallCommon - IsExternal: yes; ExtendToStructure: no; LoadBearing: yes; Reference: M_Ext_Beton_230mm

# IfcWallStandardCase: Mur de base:M_Ext_Beton_250mm, Mur de base:M_Ext_Beton_250mm:458823
In: 00_RDC CAF
Type - PredefinedType: STANDARD; Material: STR - Beton Mur 0.25 m
Type - Pset_ReinforcementBarPitchOfWall - Description: Mur beton
Pset_QuantityTakeOff - Reference: M_Ext_Beton_250mm; sets with these values: 2
Pset_WallCommon - IsExternal: yes; ExtendToStructure: no; LoadBearing: yes; Reference: M_Ext_Beton_250mm

# IfcWallStandardCase: Mur de base:M_Ext_Beton_260mm, Mur de base:M_Ext_Beton_260mm:460243
In: 00_RDC CAF
Type - PredefinedType: STANDARD; Material: STR - Beton Mur 0.26 m
Type - Pset_ReinforcementBarPitchOfWall - Description: Mur beton
Pset_QuantityTakeOff - Reference: M_Ext_Beton_260mm; sets with these values: 2
Pset_WallCommon - IsExternal: yes; ExtendToStructure: no; LoadBearing: yes; Reference: M_Ext_Beton_260mm

# IfcWallStandardCase: Mur de base:M_Ext_Beton_270mm, Mur de base:M_Ext_Beton_270mm:458822
In: 00_RDC CAF
Type - PredefinedType: STANDARD; Material: STR - Beton Mur 0.27 m
Type - Pset_ReinforcementBarPitchOfWall - Description: Mur beton
Pset_QuantityTakeOff - Reference: M_Ext_Beton_270mm; sets with these values: 2
Pset_WallCommon - IsExternal: yes; ExtendToStructure: no; LoadBearing: yes; Reference: M_Ext_Beton_270mm

# IfcWallStandardCase: Mur de base:M_Ext_Beton_280mm (2)
In: 00_RDC CAF
Type - PredefinedType: STANDARD; Material: STR - Beton Mur 0.28 m
Type - Pset_ReinforcementBarPitchOfWall - Description: Mur beton
Pset_QuantityTakeOff - Reference: M_Ext_Beton_280mm; sets with these values: 2
Pset_WallCommon - IsExternal: yes; ExtendToStructure: no; LoadBearing: yes; Reference: M_Ext_Beton_280mm
Name (Mur de base:M_Ext_Beton_280mm:...)
460447
460448

# IfcWallStandardCase: Mur de base:M_Ext_Beton_400mm, Mur de base:M_Ext_Beton_400mm:458537
In: 00_RDC CAF
Type - PredefinedType: STANDARD; Material: STR - Beton Mur 0.4 m
Type - Pset_ReinforcementBarPitchOfWall - Description: Mur beton
Pset_QuantityTakeOff - Reference: M_Ext_Beton_400mm; sets with these values: 2
Pset_WallCommon - IsExternal: yes; ExtendToStructure: no; LoadBearing: yes; Reference: M_Ext_Beton_400mm

# IfcWallStandardCase: Mur de base:M_Ext_Beton_430mm, Mur de base:M_Ext_Beton_430mm:460177
In: 00_RDC CAF
Type - PredefinedType: STANDARD; Material: STR - Beton Mur 0.43 m
Type - Pset_ReinforcementBarPitchOfWall - Description: Mur beton
Pset_QuantityTakeOff - Reference: M_Ext_Beton_430mm; sets with these values: 2
Pset_WallCommon - IsExternal: yes; ExtendToStructure: no; LoadBearing: yes; Reference: M_Ext_Beton_430mm

# IfcWallStandardCase: Mur de base:M_Ext_Beton_445mm, Mur de base:M_Ext_Beton_445mm:460176
In: 00_RDC CAF
Type - PredefinedType: STANDARD; Material: STR - Beton Mur 0.445 m
Type - Pset_ReinforcementBarPitchOfWall - Description: Mur beton
Pset_QuantityTakeOff - Reference: M_Ext_Beton_445mm; sets with these values: 2
Pset_WallCommon - IsExternal: yes; ExtendToStructure: no; LoadBearing: yes; Reference: M_Ext_Beton_445mm

# IfcWallStandardCase: Mur de base:M_Ext_Beton_550mm (2)
In: 00_RDC CAF
Type - PredefinedType: STANDARD; Material: STR - Beton Mur 0.55 m
Type - Pset_ReinforcementBarPitchOfWall - Description: Mur beton
Pset_QuantityTakeOff - Reference: M_Ext_Beton_550mm; sets with these values: 2
Pset_WallCommon - Reference: M_Ext_Beton_550mm; IsExternal: yes; ExtendToStructure: no; LoadBearing: yes
Name (Mur de base:M_Ext_Beton_550mm:...)
458533
458821

# IfcWallStandardCase: Mur de base:M_Ext_Beton_625mm, Mur de base:M_Ext_Beton_625mm:460175
In: 00_RDC CAF
Type - PredefinedType: STANDARD; Material: STR - Beton Mur 0.625 m
Type - Pset_ReinforcementBarPitchOfWall - Description: Mur beton
Pset_QuantityTakeOff - Reference: M_Ext_Beton_625mm; sets with these values: 2
Pset_WallCommon - IsExternal: yes; ExtendToStructure: no; LoadBearing: yes; Reference: M_Ext_Beton_625mm

# IfcWallStandardCase: Mur de base:M_Int_Beton_100mm, Mur de base:M_Int_Beton_100mm:460971
In: 00_RDC CAF
Type - PredefinedType: STANDARD; Material: STR - Beton Mur 0.1 m
Type - Pset_ReinforcementBarPitchOfWall - Description: Mur beton
Pset_QuantityTakeOff - Reference: M_Int_Beton_100mm; sets with these values: 2
Pset_WallCommon - ExtendToStructure: no; IsExternal: no; LoadBearing: no; Reference: M_Int_Beton_100mm

# IfcWallStandardCase: Mur de base:M_Int_Beton_140mm, Mur de base:M_Int_Beton_140mm:459306
In: 00_RDC CAF
Type - PredefinedType: STANDARD; Material: STR - Beton Mur 0.14 m
Type - Pset_ReinforcementBarPitchOfWall - Description: Mur beton
Pset_QuantityTakeOff - Reference: M_Int_Beton_140mm; sets with these values: 2
Pset_WallCommon - ExtendToStructure: no; IsExternal: no; LoadBearing: no; Reference: M_Int_Beton_140mm

# IfcWallStandardCase: Mur de base:M_Int_Beton_165mm, Mur de base:M_Int_Beton_165mm:458535
In: 00_RDC CAF
Type - PredefinedType: STANDARD; Material: STR - Beton Mur 0.165 m
Type - Pset_ReinforcementBarPitchOfWall - Description: Mur beton
Pset_QuantityTakeOff - Reference: M_Int_Beton_165mm; sets with these values: 2
Pset_WallCommon - ExtendToStructure: no; Reference: M_Int_Beton_165mm; IsExternal: no; LoadBearing: no

# IfcWallStandardCase: Mur de base:M_Int_Beton_180mm (2)
Type - PredefinedType: STANDARD; Material: STR - Beton Mur 0.18 m
Type - Pset_ReinforcementBarPitchOfWall - Description: Mur beton
Pset_QuantityTakeOff - Reference: M_Int_Beton_180mm; sets with these values: 2
Pset_WallCommon - ExtendToStructure: no; IsExternal: no; LoadBearing: no; Reference: M_Int_Beton_180mm
Name (Mur de base:M_Int_Beton_180mm:...) | In
459866 | 00_RDC CAF
459867 | 01_N1 CAF

# IfcWallStandardCase: Mur de base:M_Int_Beton_200mm (2)
In: 00_RDC CAF
Type - PredefinedType: STANDARD; Material: STR - Beton Mur 0.2 m
Type - Pset_ReinforcementBarPitchOfWall - Description: Mur beton
Pset_QuantityTakeOff - Reference: M_Int_Beton_200mm; sets with these values: 2
Pset_WallCommon - ExtendToStructure: no; IsExternal: no; Reference: M_Int_Beton_200mm
Name (Mur de base:M_Int_Beton_200mm:...) | LoadBearing
458866 | yes
459113 | no

# IfcWallStandardCase: Mur de base:M_Int_Beton_225mm (3)
In: 00_RDC CAF
Type - PredefinedType: STANDARD; Material: STR - Beton Mur 0.225 m
Type - Pset_ReinforcementBarPitchOfWall - Description: Mur beton
Pset_QuantityTakeOff - Reference: M_Int_Beton_225mm; sets with these values: 2
Pset_WallCommon - ExtendToStructure: no; LoadBearing: yes; IsExternal: no; Reference: M_Int_Beton_225mm
Name (Mur de base:M_Int_Beton_225mm:...)
458867
460305
460306

# IfcWallStandardCase: Mur de base:M_Int_Beton_300mm (3)
In: 00_RDC CAF
Type - PredefinedType: STANDARD; Material: STR - Beton Mur 0.3 m
Type - Pset_ReinforcementBarPitchOfWall - Description: Mur beton
Pset_QuantityTakeOff - Reference: M_Int_Beton_300mm; sets with these values: 2
Pset_WallCommon - IsExternal: no; Reference: M_Int_Beton_300mm
Name (Mur de base:M_Int_Beton_300mm:...) | LoadBearing = ExtendToStructure
458539 | yes
459454 | no
460136 | no

# IfcWallStandardCase: Mur de base:M_Int_Beton_325mm, Mur de base:M_Int_Beton_325mm:459114
In: 00_RDC CAF
Type - PredefinedType: STANDARD; Material: STR - Beton Mur 0.325 m
Type - Pset_ReinforcementBarPitchOfWall - Description: Mur beton
Pset_QuantityTakeOff - Reference: M_Int_Beton_325mm; sets with these values: 2
Pset_WallCommon - ExtendToStructure: no; IsExternal: no; LoadBearing: no; Reference: M_Int_Beton_325mm

# IfcWallStandardCase: Mur de base:M_Int_Beton_370mm (3)
In: 00_RDC CAF
Type - PredefinedType: STANDARD; Material: STR - Beton Mur 0.37 m
Type - Pset_ReinforcementBarPitchOfWall - Description: Mur beton
Pset_QuantityTakeOff - Reference: M_Int_Beton_370mm; sets with these values: 2
Pset_WallCommon - ExtendToStructure: no; IsExternal: no; LoadBearing: no; Reference: M_Int_Beton_370mm
Name (Mur de base:M_Int_Beton_370mm:...)
459447
459880
459881

# IfcWallStandardCase: Mur de base:M_Int_Beton_390mm, Mur de base:M_Int_Beton_390mm:458863
In: 00_RDC CAF
Type - PredefinedType: STANDARD; Material: STR - Beton Mur 0.39 m
Type - Pset_ReinforcementBarPitchOfWall - Description: Mur beton
Pset_QuantityTakeOff - Reference: M_Int_Beton_390mm; sets with these values: 2
Pset_WallCommon - ExtendToStructure: no; IsExternal: no; LoadBearing: no; Reference: M_Int_Beton_390mm

# IfcWallStandardCase: Mur de base:M_Int_Beton_400mm, Mur de base:M_Int_Beton_400mm:459112
In: 00_RDC CAF
Type - PredefinedType: STANDARD; Material: STR - Beton Mur 0.4 m
Type - Pset_ReinforcementBarPitchOfWall - Description: Mur beton
Pset_QuantityTakeOff - Reference: M_Int_Beton_400mm; sets with these values: 2
Pset_WallCommon - ExtendToStructure: no; IsExternal: no; LoadBearing: no; Reference: M_Int_Beton_400mm

# IfcWallStandardCase: Mur de base:M_Int_Beton_610mm, Mur de base:M_Int_Beton_610mm:709811
In: 00_RDC CAF
Type - PredefinedType: STANDARD; Material: STR - Beton Mur 0.61 m
Type - Pset_ReinforcementBarPitchOfWall - Description: Mur beton
Pset_QuantityTakeOff - Reference: M_Int_Beton_610mm; sets with these values: 2
Pset_WallCommon - ExtendToStructure: no; LoadBearing: yes; IsExternal: no; Reference: M_Int_Beton_610mm

# IfcWallStandardCase: Mur de base:M_Int_Beton_660mm, Mur de base:M_Int_Beton_660mm:459879
In: 00_RDC CAF
Type - PredefinedType: STANDARD; Material: STR - Beton Mur 0.66 m
Type - Pset_ReinforcementBarPitchOfWall - Description: Mur beton
Pset_QuantityTakeOff - Reference: M_Int_Beton_660mm; sets with these values: 2
Pset_WallCommon - ExtendToStructure: no; IsExternal: no; LoadBearing: no; Reference: M_Int_Beton_660mm

# IfcWindow: F_1V:F_Int_1V_Fixe (4)
In: 00_RDC CAF
Type - ParameterTakesPrecedence: no; Sizeable: no; Material: ARC - M.In - Verre, ARC - M.In - Blanc
OverallHeight: 1.2 m; OverallWidth: 0.6 m
Pset_QuantityTakeOff - Reference: F_Int_1V_Fixe
Pset_WindowCommon - IsExternal: no; Reference: F_Int_1V_Fixe
Name (F_1V:F_Int_1V_Fixe:...)
459013
459014
459015
459016
